VERSION 5.8 ;
BUSBITCHARS "[]" ;
DIVIDERCHAR "/" ;
UNITS
    DATABASE MICRONS 1000 ;
END UNITS

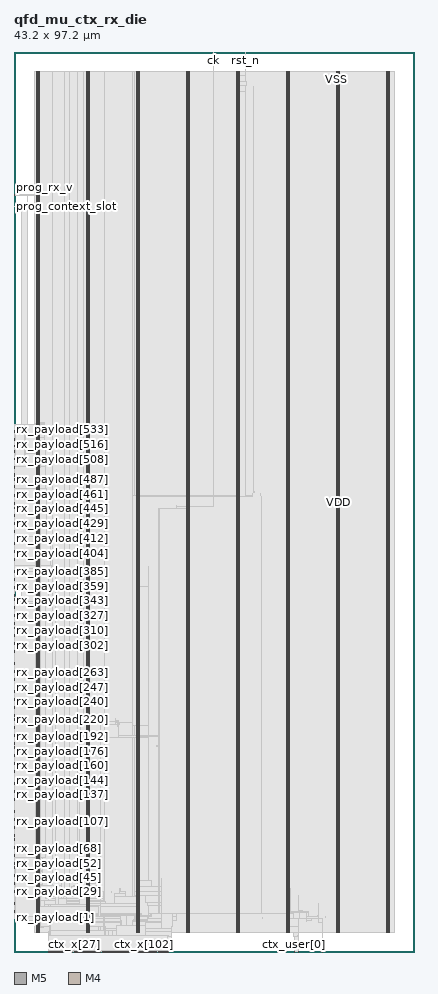
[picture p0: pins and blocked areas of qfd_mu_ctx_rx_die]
MACRO qfd_mu_ctx_rx_die
  FOREIGN qfd_mu_ctx_rx_die 0 0 ;
  CLASS BLOCK ;
  SIZE 43.2 BY 97.2 ;
  PIN ck
    DIRECTION INPUT ;
    USE SIGNAL ;
    PORT
      LAYER M5 ;
        RECT  21.504 97.116 21.528 97.2 ;
    END
  END ck
  PIN ctx_user[0]
    DIRECTION OUTPUT ;
    USE SIGNAL ;
    PORT
      LAYER M5 ;
        RECT  30.24 0 30.264 0.084 ;
    END
  END ctx_user[0]
  PIN ctx_user[1]
    DIRECTION OUTPUT ;
    USE SIGNAL ;
    PORT
      LAYER M5 ;
        RECT  30.72 0 30.744 0.084 ;
    END
  END ctx_user[1]
  PIN ctx_x[0]
    DIRECTION OUTPUT ;
    USE SIGNAL ;
    PORT
      LAYER M5 ;
        RECT  3.744 0 3.768 0.084 ;
    END
  END ctx_x[0]
  PIN ctx_x[100]
    DIRECTION OUTPUT ;
    USE SIGNAL ;
    PORT
      LAYER M5 ;
        RECT  13.824 0 13.848 0.084 ;
    END
  END ctx_x[100]
  PIN ctx_x[101]
    DIRECTION OUTPUT ;
    USE SIGNAL ;
    PORT
      LAYER M5 ;
        RECT  13.92 0 13.944 0.084 ;
    END
  END ctx_x[101]
  PIN ctx_x[102]
    DIRECTION OUTPUT ;
    USE SIGNAL ;
    PORT
      LAYER M5 ;
        RECT  14.016 0 14.04 0.084 ;
    END
  END ctx_x[102]
  PIN ctx_x[103]
    DIRECTION OUTPUT ;
    USE SIGNAL ;
    PORT
      LAYER M5 ;
        RECT  14.112 0 14.136 0.084 ;
    END
  END ctx_x[103]
  PIN ctx_x[104]
    DIRECTION OUTPUT ;
    USE SIGNAL ;
    PORT
      LAYER M5 ;
        RECT  14.208 0 14.232 0.084 ;
    END
  END ctx_x[104]
  PIN ctx_x[105]
    DIRECTION OUTPUT ;
    USE SIGNAL ;
    PORT
      LAYER M5 ;
        RECT  14.304 0 14.328 0.084 ;
    END
  END ctx_x[105]
  PIN ctx_x[106]
    DIRECTION OUTPUT ;
    USE SIGNAL ;
    PORT
      LAYER M5 ;
        RECT  14.4 0 14.424 0.084 ;
    END
  END ctx_x[106]
  PIN ctx_x[107]
    DIRECTION OUTPUT ;
    USE SIGNAL ;
    PORT
      LAYER M5 ;
        RECT  14.544 0 14.568 0.084 ;
    END
  END ctx_x[107]
  PIN ctx_x[108]
    DIRECTION OUTPUT ;
    USE SIGNAL ;
    PORT
      LAYER M5 ;
        RECT  14.64 0 14.664 0.084 ;
    END
  END ctx_x[108]
  PIN ctx_x[109]
    DIRECTION OUTPUT ;
    USE SIGNAL ;
    PORT
      LAYER M5 ;
        RECT  14.736 0 14.76 0.084 ;
    END
  END ctx_x[109]
  PIN ctx_x[10]
    DIRECTION OUTPUT ;
    USE SIGNAL ;
    PORT
      LAYER M5 ;
        RECT  4.752 0 4.776 0.084 ;
    END
  END ctx_x[10]
  PIN ctx_x[110]
    DIRECTION OUTPUT ;
    USE SIGNAL ;
    PORT
      LAYER M5 ;
        RECT  14.832 0 14.856 0.084 ;
    END
  END ctx_x[110]
  PIN ctx_x[111]
    DIRECTION OUTPUT ;
    USE SIGNAL ;
    PORT
      LAYER M5 ;
        RECT  14.928 0 14.952 0.084 ;
    END
  END ctx_x[111]
  PIN ctx_x[112]
    DIRECTION OUTPUT ;
    USE SIGNAL ;
    PORT
      LAYER M5 ;
        RECT  15.024 0 15.048 0.084 ;
    END
  END ctx_x[112]
  PIN ctx_x[113]
    DIRECTION OUTPUT ;
    USE SIGNAL ;
    PORT
      LAYER M5 ;
        RECT  15.12 0 15.144 0.084 ;
    END
  END ctx_x[113]
  PIN ctx_x[114]
    DIRECTION OUTPUT ;
    USE SIGNAL ;
    PORT
      LAYER M5 ;
        RECT  15.216 0 15.24 0.084 ;
    END
  END ctx_x[114]
  PIN ctx_x[115]
    DIRECTION OUTPUT ;
    USE SIGNAL ;
    PORT
      LAYER M5 ;
        RECT  15.312 0 15.336 0.084 ;
    END
  END ctx_x[115]
  PIN ctx_x[116]
    DIRECTION OUTPUT ;
    USE SIGNAL ;
    PORT
      LAYER M5 ;
        RECT  15.408 0 15.432 0.084 ;
    END
  END ctx_x[116]
  PIN ctx_x[117]
    DIRECTION OUTPUT ;
    USE SIGNAL ;
    PORT
      LAYER M5 ;
        RECT  15.552 0 15.576 0.084 ;
    END
  END ctx_x[117]
  PIN ctx_x[118]
    DIRECTION OUTPUT ;
    USE SIGNAL ;
    PORT
      LAYER M5 ;
        RECT  15.648 0 15.672 0.084 ;
    END
  END ctx_x[118]
  PIN ctx_x[119]
    DIRECTION OUTPUT ;
    USE SIGNAL ;
    PORT
      LAYER M5 ;
        RECT  15.744 0 15.768 0.084 ;
    END
  END ctx_x[119]
  PIN ctx_x[11]
    DIRECTION OUTPUT ;
    USE SIGNAL ;
    PORT
      LAYER M5 ;
        RECT  4.848 0 4.872 0.084 ;
    END
  END ctx_x[11]
  PIN ctx_x[120]
    DIRECTION OUTPUT ;
    USE SIGNAL ;
    PORT
      LAYER M5 ;
        RECT  15.84 0 15.864 0.084 ;
    END
  END ctx_x[120]
  PIN ctx_x[121]
    DIRECTION OUTPUT ;
    USE SIGNAL ;
    PORT
      LAYER M5 ;
        RECT  15.936 0 15.96 0.084 ;
    END
  END ctx_x[121]
  PIN ctx_x[122]
    DIRECTION OUTPUT ;
    USE SIGNAL ;
    PORT
      LAYER M5 ;
        RECT  16.032 0 16.056 0.084 ;
    END
  END ctx_x[122]
  PIN ctx_x[123]
    DIRECTION OUTPUT ;
    USE SIGNAL ;
    PORT
      LAYER M5 ;
        RECT  16.128 0 16.152 0.084 ;
    END
  END ctx_x[123]
  PIN ctx_x[124]
    DIRECTION OUTPUT ;
    USE SIGNAL ;
    PORT
      LAYER M5 ;
        RECT  16.224 0 16.248 0.084 ;
    END
  END ctx_x[124]
  PIN ctx_x[125]
    DIRECTION OUTPUT ;
    USE SIGNAL ;
    PORT
      LAYER M5 ;
        RECT  16.32 0 16.344 0.084 ;
    END
  END ctx_x[125]
  PIN ctx_x[126]
    DIRECTION OUTPUT ;
    USE SIGNAL ;
    PORT
      LAYER M5 ;
        RECT  16.416 0 16.44 0.084 ;
    END
  END ctx_x[126]
  PIN ctx_x[127]
    DIRECTION OUTPUT ;
    USE SIGNAL ;
    PORT
      LAYER M5 ;
        RECT  16.56 0 16.584 0.084 ;
    END
  END ctx_x[127]
  PIN ctx_x[128]
    DIRECTION OUTPUT ;
    USE SIGNAL ;
    PORT
      LAYER M5 ;
        RECT  16.656 0 16.68 0.084 ;
    END
  END ctx_x[128]
  PIN ctx_x[12]
    DIRECTION OUTPUT ;
    USE SIGNAL ;
    PORT
      LAYER M5 ;
        RECT  4.944 0 4.968 0.084 ;
    END
  END ctx_x[12]
  PIN ctx_x[13]
    DIRECTION OUTPUT ;
    USE SIGNAL ;
    PORT
      LAYER M5 ;
        RECT  5.04 0 5.064 0.084 ;
    END
  END ctx_x[13]
  PIN ctx_x[14]
    DIRECTION OUTPUT ;
    USE SIGNAL ;
    PORT
      LAYER M5 ;
        RECT  5.136 0 5.16 0.084 ;
    END
  END ctx_x[14]
  PIN ctx_x[15]
    DIRECTION OUTPUT ;
    USE SIGNAL ;
    PORT
      LAYER M5 ;
        RECT  5.232 0 5.256 0.084 ;
    END
  END ctx_x[15]
  PIN ctx_x[16]
    DIRECTION OUTPUT ;
    USE SIGNAL ;
    PORT
      LAYER M5 ;
        RECT  5.328 0 5.352 0.084 ;
    END
  END ctx_x[16]
  PIN ctx_x[17]
    DIRECTION OUTPUT ;
    USE SIGNAL ;
    PORT
      LAYER M5 ;
        RECT  5.472 0 5.496 0.084 ;
    END
  END ctx_x[17]
  PIN ctx_x[18]
    DIRECTION OUTPUT ;
    USE SIGNAL ;
    PORT
      LAYER M5 ;
        RECT  5.568 0 5.592 0.084 ;
    END
  END ctx_x[18]
  PIN ctx_x[19]
    DIRECTION OUTPUT ;
    USE SIGNAL ;
    PORT
      LAYER M5 ;
        RECT  5.664 0 5.688 0.084 ;
    END
  END ctx_x[19]
  PIN ctx_x[1]
    DIRECTION OUTPUT ;
    USE SIGNAL ;
    PORT
      LAYER M5 ;
        RECT  3.84 0 3.864 0.084 ;
    END
  END ctx_x[1]
  PIN ctx_x[20]
    DIRECTION OUTPUT ;
    USE SIGNAL ;
    PORT
      LAYER M5 ;
        RECT  5.76 0 5.784 0.084 ;
    END
  END ctx_x[20]
  PIN ctx_x[21]
    DIRECTION OUTPUT ;
    USE SIGNAL ;
    PORT
      LAYER M5 ;
        RECT  5.856 0 5.88 0.084 ;
    END
  END ctx_x[21]
  PIN ctx_x[22]
    DIRECTION OUTPUT ;
    USE SIGNAL ;
    PORT
      LAYER M5 ;
        RECT  5.952 0 5.976 0.084 ;
    END
  END ctx_x[22]
  PIN ctx_x[23]
    DIRECTION OUTPUT ;
    USE SIGNAL ;
    PORT
      LAYER M5 ;
        RECT  6.048 0 6.072 0.084 ;
    END
  END ctx_x[23]
  PIN ctx_x[24]
    DIRECTION OUTPUT ;
    USE SIGNAL ;
    PORT
      LAYER M5 ;
        RECT  6.144 0 6.168 0.084 ;
    END
  END ctx_x[24]
  PIN ctx_x[25]
    DIRECTION OUTPUT ;
    USE SIGNAL ;
    PORT
      LAYER M5 ;
        RECT  6.24 0 6.264 0.084 ;
    END
  END ctx_x[25]
  PIN ctx_x[26]
    DIRECTION OUTPUT ;
    USE SIGNAL ;
    PORT
      LAYER M5 ;
        RECT  6.336 0 6.36 0.084 ;
    END
  END ctx_x[26]
  PIN ctx_x[27]
    DIRECTION OUTPUT ;
    USE SIGNAL ;
    PORT
      LAYER M5 ;
        RECT  6.48 0 6.504 0.084 ;
    END
  END ctx_x[27]
  PIN ctx_x[28]
    DIRECTION OUTPUT ;
    USE SIGNAL ;
    PORT
      LAYER M5 ;
        RECT  6.576 0 6.6 0.084 ;
    END
  END ctx_x[28]
  PIN ctx_x[29]
    DIRECTION OUTPUT ;
    USE SIGNAL ;
    PORT
      LAYER M5 ;
        RECT  6.672 0 6.696 0.084 ;
    END
  END ctx_x[29]
  PIN ctx_x[2]
    DIRECTION OUTPUT ;
    USE SIGNAL ;
    PORT
      LAYER M5 ;
        RECT  3.936 0 3.96 0.084 ;
    END
  END ctx_x[2]
  PIN ctx_x[30]
    DIRECTION OUTPUT ;
    USE SIGNAL ;
    PORT
      LAYER M5 ;
        RECT  6.768 0 6.792 0.084 ;
    END
  END ctx_x[30]
  PIN ctx_x[31]
    DIRECTION OUTPUT ;
    USE SIGNAL ;
    PORT
      LAYER M5 ;
        RECT  6.864 0 6.888 0.084 ;
    END
  END ctx_x[31]
  PIN ctx_x[32]
    DIRECTION OUTPUT ;
    USE SIGNAL ;
    PORT
      LAYER M5 ;
        RECT  6.96 0 6.984 0.084 ;
    END
  END ctx_x[32]
  PIN ctx_x[33]
    DIRECTION OUTPUT ;
    USE SIGNAL ;
    PORT
      LAYER M5 ;
        RECT  7.056 0 7.08 0.084 ;
    END
  END ctx_x[33]
  PIN ctx_x[34]
    DIRECTION OUTPUT ;
    USE SIGNAL ;
    PORT
      LAYER M5 ;
        RECT  7.152 0 7.176 0.084 ;
    END
  END ctx_x[34]
  PIN ctx_x[35]
    DIRECTION OUTPUT ;
    USE SIGNAL ;
    PORT
      LAYER M5 ;
        RECT  7.248 0 7.272 0.084 ;
    END
  END ctx_x[35]
  PIN ctx_x[36]
    DIRECTION OUTPUT ;
    USE SIGNAL ;
    PORT
      LAYER M5 ;
        RECT  7.344 0 7.368 0.084 ;
    END
  END ctx_x[36]
  PIN ctx_x[37]
    DIRECTION OUTPUT ;
    USE SIGNAL ;
    PORT
      LAYER M5 ;
        RECT  7.488 0 7.512 0.084 ;
    END
  END ctx_x[37]
  PIN ctx_x[38]
    DIRECTION OUTPUT ;
    USE SIGNAL ;
    PORT
      LAYER M5 ;
        RECT  7.584 0 7.608 0.084 ;
    END
  END ctx_x[38]
  PIN ctx_x[39]
    DIRECTION OUTPUT ;
    USE SIGNAL ;
    PORT
      LAYER M5 ;
        RECT  7.68 0 7.704 0.084 ;
    END
  END ctx_x[39]
  PIN ctx_x[3]
    DIRECTION OUTPUT ;
    USE SIGNAL ;
    PORT
      LAYER M5 ;
        RECT  4.032 0 4.056 0.084 ;
    END
  END ctx_x[3]
  PIN ctx_x[40]
    DIRECTION OUTPUT ;
    USE SIGNAL ;
    PORT
      LAYER M5 ;
        RECT  7.776 0 7.8 0.084 ;
    END
  END ctx_x[40]
  PIN ctx_x[41]
    DIRECTION OUTPUT ;
    USE SIGNAL ;
    PORT
      LAYER M5 ;
        RECT  7.872 0 7.896 0.084 ;
    END
  END ctx_x[41]
  PIN ctx_x[42]
    DIRECTION OUTPUT ;
    USE SIGNAL ;
    PORT
      LAYER M5 ;
        RECT  7.968 0 7.992 0.084 ;
    END
  END ctx_x[42]
  PIN ctx_x[43]
    DIRECTION OUTPUT ;
    USE SIGNAL ;
    PORT
      LAYER M5 ;
        RECT  8.064 0 8.088 0.084 ;
    END
  END ctx_x[43]
  PIN ctx_x[44]
    DIRECTION OUTPUT ;
    USE SIGNAL ;
    PORT
      LAYER M5 ;
        RECT  8.16 0 8.184 0.084 ;
    END
  END ctx_x[44]
  PIN ctx_x[45]
    DIRECTION OUTPUT ;
    USE SIGNAL ;
    PORT
      LAYER M5 ;
        RECT  8.256 0 8.28 0.084 ;
    END
  END ctx_x[45]
  PIN ctx_x[46]
    DIRECTION OUTPUT ;
    USE SIGNAL ;
    PORT
      LAYER M5 ;
        RECT  8.352 0 8.376 0.084 ;
    END
  END ctx_x[46]
  PIN ctx_x[47]
    DIRECTION OUTPUT ;
    USE SIGNAL ;
    PORT
      LAYER M5 ;
        RECT  8.496 0 8.52 0.084 ;
    END
  END ctx_x[47]
  PIN ctx_x[48]
    DIRECTION OUTPUT ;
    USE SIGNAL ;
    PORT
      LAYER M5 ;
        RECT  8.592 0 8.616 0.084 ;
    END
  END ctx_x[48]
  PIN ctx_x[49]
    DIRECTION OUTPUT ;
    USE SIGNAL ;
    PORT
      LAYER M5 ;
        RECT  8.688 0 8.712 0.084 ;
    END
  END ctx_x[49]
  PIN ctx_x[4]
    DIRECTION OUTPUT ;
    USE SIGNAL ;
    PORT
      LAYER M5 ;
        RECT  4.128 0 4.152 0.084 ;
    END
  END ctx_x[4]
  PIN ctx_x[50]
    DIRECTION OUTPUT ;
    USE SIGNAL ;
    PORT
      LAYER M5 ;
        RECT  8.784 0 8.808 0.084 ;
    END
  END ctx_x[50]
  PIN ctx_x[51]
    DIRECTION OUTPUT ;
    USE SIGNAL ;
    PORT
      LAYER M5 ;
        RECT  8.88 0 8.904 0.084 ;
    END
  END ctx_x[51]
  PIN ctx_x[52]
    DIRECTION OUTPUT ;
    USE SIGNAL ;
    PORT
      LAYER M5 ;
        RECT  8.976 0 9 0.084 ;
    END
  END ctx_x[52]
  PIN ctx_x[53]
    DIRECTION OUTPUT ;
    USE SIGNAL ;
    PORT
      LAYER M5 ;
        RECT  9.072 0 9.096 0.084 ;
    END
  END ctx_x[53]
  PIN ctx_x[54]
    DIRECTION OUTPUT ;
    USE SIGNAL ;
    PORT
      LAYER M5 ;
        RECT  9.168 0 9.192 0.084 ;
    END
  END ctx_x[54]
  PIN ctx_x[55]
    DIRECTION OUTPUT ;
    USE SIGNAL ;
    PORT
      LAYER M5 ;
        RECT  9.264 0 9.288 0.084 ;
    END
  END ctx_x[55]
  PIN ctx_x[56]
    DIRECTION OUTPUT ;
    USE SIGNAL ;
    PORT
      LAYER M5 ;
        RECT  9.36 0 9.384 0.084 ;
    END
  END ctx_x[56]
  PIN ctx_x[57]
    DIRECTION OUTPUT ;
    USE SIGNAL ;
    PORT
      LAYER M5 ;
        RECT  9.504 0 9.528 0.084 ;
    END
  END ctx_x[57]
  PIN ctx_x[58]
    DIRECTION OUTPUT ;
    USE SIGNAL ;
    PORT
      LAYER M5 ;
        RECT  9.6 0 9.624 0.084 ;
    END
  END ctx_x[58]
  PIN ctx_x[59]
    DIRECTION OUTPUT ;
    USE SIGNAL ;
    PORT
      LAYER M5 ;
        RECT  9.696 0 9.72 0.084 ;
    END
  END ctx_x[59]
  PIN ctx_x[5]
    DIRECTION OUTPUT ;
    USE SIGNAL ;
    PORT
      LAYER M5 ;
        RECT  4.224 0 4.248 0.084 ;
    END
  END ctx_x[5]
  PIN ctx_x[60]
    DIRECTION OUTPUT ;
    USE SIGNAL ;
    PORT
      LAYER M5 ;
        RECT  9.792 0 9.816 0.084 ;
    END
  END ctx_x[60]
  PIN ctx_x[61]
    DIRECTION OUTPUT ;
    USE SIGNAL ;
    PORT
      LAYER M5 ;
        RECT  9.888 0 9.912 0.084 ;
    END
  END ctx_x[61]
  PIN ctx_x[62]
    DIRECTION OUTPUT ;
    USE SIGNAL ;
    PORT
      LAYER M5 ;
        RECT  9.984 0 10.008 0.084 ;
    END
  END ctx_x[62]
  PIN ctx_x[63]
    DIRECTION OUTPUT ;
    USE SIGNAL ;
    PORT
      LAYER M5 ;
        RECT  10.08 0 10.104 0.084 ;
    END
  END ctx_x[63]
  PIN ctx_x[64]
    DIRECTION OUTPUT ;
    USE SIGNAL ;
    PORT
      LAYER M5 ;
        RECT  10.176 0 10.2 0.084 ;
    END
  END ctx_x[64]
  PIN ctx_x[65]
    DIRECTION OUTPUT ;
    USE SIGNAL ;
    PORT
      LAYER M5 ;
        RECT  10.272 0 10.296 0.084 ;
    END
  END ctx_x[65]
  PIN ctx_x[66]
    DIRECTION OUTPUT ;
    USE SIGNAL ;
    PORT
      LAYER M5 ;
        RECT  10.368 0 10.392 0.084 ;
    END
  END ctx_x[66]
  PIN ctx_x[67]
    DIRECTION OUTPUT ;
    USE SIGNAL ;
    PORT
      LAYER M5 ;
        RECT  10.512 0 10.536 0.084 ;
    END
  END ctx_x[67]
  PIN ctx_x[68]
    DIRECTION OUTPUT ;
    USE SIGNAL ;
    PORT
      LAYER M5 ;
        RECT  10.608 0 10.632 0.084 ;
    END
  END ctx_x[68]
  PIN ctx_x[69]
    DIRECTION OUTPUT ;
    USE SIGNAL ;
    PORT
      LAYER M5 ;
        RECT  10.704 0 10.728 0.084 ;
    END
  END ctx_x[69]
  PIN ctx_x[6]
    DIRECTION OUTPUT ;
    USE SIGNAL ;
    PORT
      LAYER M5 ;
        RECT  4.32 0 4.344 0.084 ;
    END
  END ctx_x[6]
  PIN ctx_x[70]
    DIRECTION OUTPUT ;
    USE SIGNAL ;
    PORT
      LAYER M5 ;
        RECT  10.8 0 10.824 0.084 ;
    END
  END ctx_x[70]
  PIN ctx_x[71]
    DIRECTION OUTPUT ;
    USE SIGNAL ;
    PORT
      LAYER M5 ;
        RECT  10.896 0 10.92 0.084 ;
    END
  END ctx_x[71]
  PIN ctx_x[72]
    DIRECTION OUTPUT ;
    USE SIGNAL ;
    PORT
      LAYER M5 ;
        RECT  10.992 0 11.016 0.084 ;
    END
  END ctx_x[72]
  PIN ctx_x[73]
    DIRECTION OUTPUT ;
    USE SIGNAL ;
    PORT
      LAYER M5 ;
        RECT  11.088 0 11.112 0.084 ;
    END
  END ctx_x[73]
  PIN ctx_x[74]
    DIRECTION OUTPUT ;
    USE SIGNAL ;
    PORT
      LAYER M5 ;
        RECT  11.184 0 11.208 0.084 ;
    END
  END ctx_x[74]
  PIN ctx_x[75]
    DIRECTION OUTPUT ;
    USE SIGNAL ;
    PORT
      LAYER M5 ;
        RECT  11.28 0 11.304 0.084 ;
    END
  END ctx_x[75]
  PIN ctx_x[76]
    DIRECTION OUTPUT ;
    USE SIGNAL ;
    PORT
      LAYER M5 ;
        RECT  11.376 0 11.4 0.084 ;
    END
  END ctx_x[76]
  PIN ctx_x[77]
    DIRECTION OUTPUT ;
    USE SIGNAL ;
    PORT
      LAYER M5 ;
        RECT  11.52 0 11.544 0.084 ;
    END
  END ctx_x[77]
  PIN ctx_x[78]
    DIRECTION OUTPUT ;
    USE SIGNAL ;
    PORT
      LAYER M5 ;
        RECT  11.616 0 11.64 0.084 ;
    END
  END ctx_x[78]
  PIN ctx_x[79]
    DIRECTION OUTPUT ;
    USE SIGNAL ;
    PORT
      LAYER M5 ;
        RECT  11.712 0 11.736 0.084 ;
    END
  END ctx_x[79]
  PIN ctx_x[7]
    DIRECTION OUTPUT ;
    USE SIGNAL ;
    PORT
      LAYER M5 ;
        RECT  4.464 0 4.488 0.084 ;
    END
  END ctx_x[7]
  PIN ctx_x[80]
    DIRECTION OUTPUT ;
    USE SIGNAL ;
    PORT
      LAYER M5 ;
        RECT  11.808 0 11.832 0.084 ;
    END
  END ctx_x[80]
  PIN ctx_x[81]
    DIRECTION OUTPUT ;
    USE SIGNAL ;
    PORT
      LAYER M5 ;
        RECT  11.904 0 11.928 0.084 ;
    END
  END ctx_x[81]
  PIN ctx_x[82]
    DIRECTION OUTPUT ;
    USE SIGNAL ;
    PORT
      LAYER M5 ;
        RECT  12 0 12.024 0.084 ;
    END
  END ctx_x[82]
  PIN ctx_x[83]
    DIRECTION OUTPUT ;
    USE SIGNAL ;
    PORT
      LAYER M5 ;
        RECT  12.096 0 12.12 0.084 ;
    END
  END ctx_x[83]
  PIN ctx_x[84]
    DIRECTION OUTPUT ;
    USE SIGNAL ;
    PORT
      LAYER M5 ;
        RECT  12.192 0 12.216 0.084 ;
    END
  END ctx_x[84]
  PIN ctx_x[85]
    DIRECTION OUTPUT ;
    USE SIGNAL ;
    PORT
      LAYER M5 ;
        RECT  12.288 0 12.312 0.084 ;
    END
  END ctx_x[85]
  PIN ctx_x[86]
    DIRECTION OUTPUT ;
    USE SIGNAL ;
    PORT
      LAYER M5 ;
        RECT  12.384 0 12.408 0.084 ;
    END
  END ctx_x[86]
  PIN ctx_x[87]
    DIRECTION OUTPUT ;
    USE SIGNAL ;
    PORT
      LAYER M5 ;
        RECT  12.528 0 12.552 0.084 ;
    END
  END ctx_x[87]
  PIN ctx_x[88]
    DIRECTION OUTPUT ;
    USE SIGNAL ;
    PORT
      LAYER M5 ;
        RECT  12.624 0 12.648 0.084 ;
    END
  END ctx_x[88]
  PIN ctx_x[89]
    DIRECTION OUTPUT ;
    USE SIGNAL ;
    PORT
      LAYER M5 ;
        RECT  12.72 0 12.744 0.084 ;
    END
  END ctx_x[89]
  PIN ctx_x[8]
    DIRECTION OUTPUT ;
    USE SIGNAL ;
    PORT
      LAYER M5 ;
        RECT  4.56 0 4.584 0.084 ;
    END
  END ctx_x[8]
  PIN ctx_x[90]
    DIRECTION OUTPUT ;
    USE SIGNAL ;
    PORT
      LAYER M5 ;
        RECT  12.816 0 12.84 0.084 ;
    END
  END ctx_x[90]
  PIN ctx_x[91]
    DIRECTION OUTPUT ;
    USE SIGNAL ;
    PORT
      LAYER M5 ;
        RECT  12.912 0 12.936 0.084 ;
    END
  END ctx_x[91]
  PIN ctx_x[92]
    DIRECTION OUTPUT ;
    USE SIGNAL ;
    PORT
      LAYER M5 ;
        RECT  13.008 0 13.032 0.084 ;
    END
  END ctx_x[92]
  PIN ctx_x[93]
    DIRECTION OUTPUT ;
    USE SIGNAL ;
    PORT
      LAYER M5 ;
        RECT  13.104 0 13.128 0.084 ;
    END
  END ctx_x[93]
  PIN ctx_x[94]
    DIRECTION OUTPUT ;
    USE SIGNAL ;
    PORT
      LAYER M5 ;
        RECT  13.2 0 13.224 0.084 ;
    END
  END ctx_x[94]
  PIN ctx_x[95]
    DIRECTION OUTPUT ;
    USE SIGNAL ;
    PORT
      LAYER M5 ;
        RECT  13.296 0 13.32 0.084 ;
    END
  END ctx_x[95]
  PIN ctx_x[96]
    DIRECTION OUTPUT ;
    USE SIGNAL ;
    PORT
      LAYER M5 ;
        RECT  13.392 0 13.416 0.084 ;
    END
  END ctx_x[96]
  PIN ctx_x[97]
    DIRECTION OUTPUT ;
    USE SIGNAL ;
    PORT
      LAYER M5 ;
        RECT  13.536 0 13.56 0.084 ;
    END
  END ctx_x[97]
  PIN ctx_x[98]
    DIRECTION OUTPUT ;
    USE SIGNAL ;
    PORT
      LAYER M5 ;
        RECT  13.632 0 13.656 0.084 ;
    END
  END ctx_x[98]
  PIN ctx_x[99]
    DIRECTION OUTPUT ;
    USE SIGNAL ;
    PORT
      LAYER M5 ;
        RECT  13.728 0 13.752 0.084 ;
    END
  END ctx_x[99]
  PIN ctx_x[9]
    DIRECTION OUTPUT ;
    USE SIGNAL ;
    PORT
      LAYER M5 ;
        RECT  4.656 0 4.68 0.084 ;
    END
  END ctx_x[9]
  PIN mu_fault
    DIRECTION OUTPUT ;
    USE SIGNAL ;
    PORT
      LAYER M5 ;
        RECT  33.312 0 33.336 0.084 ;
    END
  END mu_fault
  PIN prog_context_slot
    DIRECTION INPUT ;
    USE SIGNAL ;
    PORT
      LAYER M4 ;
        RECT  0 80.544 0.084 80.568 ;
    END
  END prog_context_slot
  PIN prog_rx_v
    DIRECTION INPUT ;
    USE SIGNAL ;
    PORT
      LAYER M4 ;
        RECT  0 81.744 0.084 81.768 ;
    END
  END prog_rx_v
  PIN rst_n
    DIRECTION INPUT ;
    USE SIGNAL ;
    PORT
      LAYER M5 ;
        RECT  25.008 97.116 25.032 97.2 ;
    END
  END rst_n
  PIN rx_payload[0]
    DIRECTION INPUT ;
    USE SIGNAL ;
    PORT
      LAYER M4 ;
        RECT  0 3.648 0.084 3.672 ;
    END
  END rx_payload[0]
  PIN rx_payload[100]
    DIRECTION INPUT ;
    USE SIGNAL ;
    PORT
      LAYER M4 ;
        RECT  0 13.392 0.084 13.416 ;
    END
  END rx_payload[100]
  PIN rx_payload[101]
    DIRECTION INPUT ;
    USE SIGNAL ;
    PORT
      LAYER M4 ;
        RECT  0 13.488 0.084 13.512 ;
    END
  END rx_payload[101]
  PIN rx_payload[102]
    DIRECTION INPUT ;
    USE SIGNAL ;
    PORT
      LAYER M4 ;
        RECT  0 13.584 0.084 13.608 ;
    END
  END rx_payload[102]
  PIN rx_payload[103]
    DIRECTION INPUT ;
    USE SIGNAL ;
    PORT
      LAYER M4 ;
        RECT  0 13.68 0.084 13.704 ;
    END
  END rx_payload[103]
  PIN rx_payload[104]
    DIRECTION INPUT ;
    USE SIGNAL ;
    PORT
      LAYER M4 ;
        RECT  0 13.776 0.084 13.8 ;
    END
  END rx_payload[104]
  PIN rx_payload[105]
    DIRECTION INPUT ;
    USE SIGNAL ;
    PORT
      LAYER M4 ;
        RECT  0 13.872 0.084 13.896 ;
    END
  END rx_payload[105]
  PIN rx_payload[106]
    DIRECTION INPUT ;
    USE SIGNAL ;
    PORT
      LAYER M4 ;
        RECT  0 13.968 0.084 13.992 ;
    END
  END rx_payload[106]
  PIN rx_payload[107]
    DIRECTION INPUT ;
    USE SIGNAL ;
    PORT
      LAYER M4 ;
        RECT  0 14.064 0.084 14.088 ;
    END
  END rx_payload[107]
  PIN rx_payload[108]
    DIRECTION INPUT ;
    USE SIGNAL ;
    PORT
      LAYER M4 ;
        RECT  0 14.16 0.084 14.184 ;
    END
  END rx_payload[108]
  PIN rx_payload[109]
    DIRECTION INPUT ;
    USE SIGNAL ;
    PORT
      LAYER M4 ;
        RECT  0 14.256 0.084 14.28 ;
    END
  END rx_payload[109]
  PIN rx_payload[10]
    DIRECTION INPUT ;
    USE SIGNAL ;
    PORT
      LAYER M4 ;
        RECT  0 4.608 0.084 4.632 ;
    END
  END rx_payload[10]
  PIN rx_payload[110]
    DIRECTION INPUT ;
    USE SIGNAL ;
    PORT
      LAYER M4 ;
        RECT  0 14.352 0.084 14.376 ;
    END
  END rx_payload[110]
  PIN rx_payload[111]
    DIRECTION INPUT ;
    USE SIGNAL ;
    PORT
      LAYER M4 ;
        RECT  0 14.448 0.084 14.472 ;
    END
  END rx_payload[111]
  PIN rx_payload[112]
    DIRECTION INPUT ;
    USE SIGNAL ;
    PORT
      LAYER M4 ;
        RECT  0 14.544 0.084 14.568 ;
    END
  END rx_payload[112]
  PIN rx_payload[113]
    DIRECTION INPUT ;
    USE SIGNAL ;
    PORT
      LAYER M4 ;
        RECT  0 14.64 0.084 14.664 ;
    END
  END rx_payload[113]
  PIN rx_payload[114]
    DIRECTION INPUT ;
    USE SIGNAL ;
    PORT
      LAYER M4 ;
        RECT  0 14.736 0.084 14.76 ;
    END
  END rx_payload[114]
  PIN rx_payload[115]
    DIRECTION INPUT ;
    USE SIGNAL ;
    PORT
      LAYER M4 ;
        RECT  0 14.832 0.084 14.856 ;
    END
  END rx_payload[115]
  PIN rx_payload[116]
    DIRECTION INPUT ;
    USE SIGNAL ;
    PORT
      LAYER M4 ;
        RECT  0 14.928 0.084 14.952 ;
    END
  END rx_payload[116]
  PIN rx_payload[117]
    DIRECTION INPUT ;
    USE SIGNAL ;
    PORT
      LAYER M4 ;
        RECT  0 15.024 0.084 15.048 ;
    END
  END rx_payload[117]
  PIN rx_payload[118]
    DIRECTION INPUT ;
    USE SIGNAL ;
    PORT
      LAYER M4 ;
        RECT  0 15.12 0.084 15.144 ;
    END
  END rx_payload[118]
  PIN rx_payload[119]
    DIRECTION INPUT ;
    USE SIGNAL ;
    PORT
      LAYER M4 ;
        RECT  0 15.216 0.084 15.24 ;
    END
  END rx_payload[119]
  PIN rx_payload[11]
    DIRECTION INPUT ;
    USE SIGNAL ;
    PORT
      LAYER M4 ;
        RECT  0 4.704 0.084 4.728 ;
    END
  END rx_payload[11]
  PIN rx_payload[120]
    DIRECTION INPUT ;
    USE SIGNAL ;
    PORT
      LAYER M4 ;
        RECT  0 15.312 0.084 15.336 ;
    END
  END rx_payload[120]
  PIN rx_payload[121]
    DIRECTION INPUT ;
    USE SIGNAL ;
    PORT
      LAYER M4 ;
        RECT  0 15.408 0.084 15.432 ;
    END
  END rx_payload[121]
  PIN rx_payload[122]
    DIRECTION INPUT ;
    USE SIGNAL ;
    PORT
      LAYER M4 ;
        RECT  0 15.504 0.084 15.528 ;
    END
  END rx_payload[122]
  PIN rx_payload[123]
    DIRECTION INPUT ;
    USE SIGNAL ;
    PORT
      LAYER M4 ;
        RECT  0 15.6 0.084 15.624 ;
    END
  END rx_payload[123]
  PIN rx_payload[124]
    DIRECTION INPUT ;
    USE SIGNAL ;
    PORT
      LAYER M4 ;
        RECT  0 15.744 0.084 15.768 ;
    END
  END rx_payload[124]
  PIN rx_payload[125]
    DIRECTION INPUT ;
    USE SIGNAL ;
    PORT
      LAYER M4 ;
        RECT  0 15.84 0.084 15.864 ;
    END
  END rx_payload[125]
  PIN rx_payload[126]
    DIRECTION INPUT ;
    USE SIGNAL ;
    PORT
      LAYER M4 ;
        RECT  0 15.936 0.084 15.96 ;
    END
  END rx_payload[126]
  PIN rx_payload[127]
    DIRECTION INPUT ;
    USE SIGNAL ;
    PORT
      LAYER M4 ;
        RECT  0 16.032 0.084 16.056 ;
    END
  END rx_payload[127]
  PIN rx_payload[128]
    DIRECTION INPUT ;
    USE SIGNAL ;
    PORT
      LAYER M4 ;
        RECT  0 16.128 0.084 16.152 ;
    END
  END rx_payload[128]
  PIN rx_payload[129]
    DIRECTION INPUT ;
    USE SIGNAL ;
    PORT
      LAYER M4 ;
        RECT  0 16.224 0.084 16.248 ;
    END
  END rx_payload[129]
  PIN rx_payload[12]
    DIRECTION INPUT ;
    USE SIGNAL ;
    PORT
      LAYER M4 ;
        RECT  0 4.8 0.084 4.824 ;
    END
  END rx_payload[12]
  PIN rx_payload[130]
    DIRECTION INPUT ;
    USE SIGNAL ;
    PORT
      LAYER M4 ;
        RECT  0 16.32 0.084 16.344 ;
    END
  END rx_payload[130]
  PIN rx_payload[131]
    DIRECTION INPUT ;
    USE SIGNAL ;
    PORT
      LAYER M4 ;
        RECT  0 16.416 0.084 16.44 ;
    END
  END rx_payload[131]
  PIN rx_payload[132]
    DIRECTION INPUT ;
    USE SIGNAL ;
    PORT
      LAYER M4 ;
        RECT  0 16.512 0.084 16.536 ;
    END
  END rx_payload[132]
  PIN rx_payload[133]
    DIRECTION INPUT ;
    USE SIGNAL ;
    PORT
      LAYER M4 ;
        RECT  0 16.608 0.084 16.632 ;
    END
  END rx_payload[133]
  PIN rx_payload[134]
    DIRECTION INPUT ;
    USE SIGNAL ;
    PORT
      LAYER M4 ;
        RECT  0 16.704 0.084 16.728 ;
    END
  END rx_payload[134]
  PIN rx_payload[135]
    DIRECTION INPUT ;
    USE SIGNAL ;
    PORT
      LAYER M4 ;
        RECT  0 16.8 0.084 16.824 ;
    END
  END rx_payload[135]
  PIN rx_payload[136]
    DIRECTION INPUT ;
    USE SIGNAL ;
    PORT
      LAYER M4 ;
        RECT  0 16.896 0.084 16.92 ;
    END
  END rx_payload[136]
  PIN rx_payload[137]
    DIRECTION INPUT ;
    USE SIGNAL ;
    PORT
      LAYER M4 ;
        RECT  0 16.992 0.084 17.016 ;
    END
  END rx_payload[137]
  PIN rx_payload[138]
    DIRECTION INPUT ;
    USE SIGNAL ;
    PORT
      LAYER M4 ;
        RECT  0 17.088 0.084 17.112 ;
    END
  END rx_payload[138]
  PIN rx_payload[139]
    DIRECTION INPUT ;
    USE SIGNAL ;
    PORT
      LAYER M4 ;
        RECT  0 17.184 0.084 17.208 ;
    END
  END rx_payload[139]
  PIN rx_payload[13]
    DIRECTION INPUT ;
    USE SIGNAL ;
    PORT
      LAYER M4 ;
        RECT  0 4.896 0.084 4.92 ;
    END
  END rx_payload[13]
  PIN rx_payload[140]
    DIRECTION INPUT ;
    USE SIGNAL ;
    PORT
      LAYER M4 ;
        RECT  0 17.28 0.084 17.304 ;
    END
  END rx_payload[140]
  PIN rx_payload[141]
    DIRECTION INPUT ;
    USE SIGNAL ;
    PORT
      LAYER M4 ;
        RECT  0 17.376 0.084 17.4 ;
    END
  END rx_payload[141]
  PIN rx_payload[142]
    DIRECTION INPUT ;
    USE SIGNAL ;
    PORT
      LAYER M4 ;
        RECT  0 17.472 0.084 17.496 ;
    END
  END rx_payload[142]
  PIN rx_payload[143]
    DIRECTION INPUT ;
    USE SIGNAL ;
    PORT
      LAYER M4 ;
        RECT  0 17.568 0.084 17.592 ;
    END
  END rx_payload[143]
  PIN rx_payload[144]
    DIRECTION INPUT ;
    USE SIGNAL ;
    PORT
      LAYER M4 ;
        RECT  0 17.664 0.084 17.688 ;
    END
  END rx_payload[144]
  PIN rx_payload[145]
    DIRECTION INPUT ;
    USE SIGNAL ;
    PORT
      LAYER M4 ;
        RECT  0 17.76 0.084 17.784 ;
    END
  END rx_payload[145]
  PIN rx_payload[146]
    DIRECTION INPUT ;
    USE SIGNAL ;
    PORT
      LAYER M4 ;
        RECT  0 17.856 0.084 17.88 ;
    END
  END rx_payload[146]
  PIN rx_payload[147]
    DIRECTION INPUT ;
    USE SIGNAL ;
    PORT
      LAYER M4 ;
        RECT  0 17.952 0.084 17.976 ;
    END
  END rx_payload[147]
  PIN rx_payload[148]
    DIRECTION INPUT ;
    USE SIGNAL ;
    PORT
      LAYER M4 ;
        RECT  0 18.048 0.084 18.072 ;
    END
  END rx_payload[148]
  PIN rx_payload[149]
    DIRECTION INPUT ;
    USE SIGNAL ;
    PORT
      LAYER M4 ;
        RECT  0 18.144 0.084 18.168 ;
    END
  END rx_payload[149]
  PIN rx_payload[14]
    DIRECTION INPUT ;
    USE SIGNAL ;
    PORT
      LAYER M4 ;
        RECT  0 4.992 0.084 5.016 ;
    END
  END rx_payload[14]
  PIN rx_payload[150]
    DIRECTION INPUT ;
    USE SIGNAL ;
    PORT
      LAYER M4 ;
        RECT  0 18.24 0.084 18.264 ;
    END
  END rx_payload[150]
  PIN rx_payload[151]
    DIRECTION INPUT ;
    USE SIGNAL ;
    PORT
      LAYER M4 ;
        RECT  0 18.336 0.084 18.36 ;
    END
  END rx_payload[151]
  PIN rx_payload[152]
    DIRECTION INPUT ;
    USE SIGNAL ;
    PORT
      LAYER M4 ;
        RECT  0 18.432 0.084 18.456 ;
    END
  END rx_payload[152]
  PIN rx_payload[153]
    DIRECTION INPUT ;
    USE SIGNAL ;
    PORT
      LAYER M4 ;
        RECT  0 18.528 0.084 18.552 ;
    END
  END rx_payload[153]
  PIN rx_payload[154]
    DIRECTION INPUT ;
    USE SIGNAL ;
    PORT
      LAYER M4 ;
        RECT  0 18.624 0.084 18.648 ;
    END
  END rx_payload[154]
  PIN rx_payload[155]
    DIRECTION INPUT ;
    USE SIGNAL ;
    PORT
      LAYER M4 ;
        RECT  0 18.72 0.084 18.744 ;
    END
  END rx_payload[155]
  PIN rx_payload[156]
    DIRECTION INPUT ;
    USE SIGNAL ;
    PORT
      LAYER M4 ;
        RECT  0 18.816 0.084 18.84 ;
    END
  END rx_payload[156]
  PIN rx_payload[157]
    DIRECTION INPUT ;
    USE SIGNAL ;
    PORT
      LAYER M4 ;
        RECT  0 18.96 0.084 18.984 ;
    END
  END rx_payload[157]
  PIN rx_payload[158]
    DIRECTION INPUT ;
    USE SIGNAL ;
    PORT
      LAYER M4 ;
        RECT  0 19.056 0.084 19.08 ;
    END
  END rx_payload[158]
  PIN rx_payload[159]
    DIRECTION INPUT ;
    USE SIGNAL ;
    PORT
      LAYER M4 ;
        RECT  0 19.152 0.084 19.176 ;
    END
  END rx_payload[159]
  PIN rx_payload[15]
    DIRECTION INPUT ;
    USE SIGNAL ;
    PORT
      LAYER M4 ;
        RECT  0 5.088 0.084 5.112 ;
    END
  END rx_payload[15]
  PIN rx_payload[160]
    DIRECTION INPUT ;
    USE SIGNAL ;
    PORT
      LAYER M4 ;
        RECT  0 19.248 0.084 19.272 ;
    END
  END rx_payload[160]
  PIN rx_payload[161]
    DIRECTION INPUT ;
    USE SIGNAL ;
    PORT
      LAYER M4 ;
        RECT  0 19.344 0.084 19.368 ;
    END
  END rx_payload[161]
  PIN rx_payload[162]
    DIRECTION INPUT ;
    USE SIGNAL ;
    PORT
      LAYER M4 ;
        RECT  0 19.44 0.084 19.464 ;
    END
  END rx_payload[162]
  PIN rx_payload[163]
    DIRECTION INPUT ;
    USE SIGNAL ;
    PORT
      LAYER M4 ;
        RECT  0 19.536 0.084 19.56 ;
    END
  END rx_payload[163]
  PIN rx_payload[164]
    DIRECTION INPUT ;
    USE SIGNAL ;
    PORT
      LAYER M4 ;
        RECT  0 19.632 0.084 19.656 ;
    END
  END rx_payload[164]
  PIN rx_payload[165]
    DIRECTION INPUT ;
    USE SIGNAL ;
    PORT
      LAYER M4 ;
        RECT  0 19.728 0.084 19.752 ;
    END
  END rx_payload[165]
  PIN rx_payload[166]
    DIRECTION INPUT ;
    USE SIGNAL ;
    PORT
      LAYER M4 ;
        RECT  0 19.824 0.084 19.848 ;
    END
  END rx_payload[166]
  PIN rx_payload[167]
    DIRECTION INPUT ;
    USE SIGNAL ;
    PORT
      LAYER M4 ;
        RECT  0 19.92 0.084 19.944 ;
    END
  END rx_payload[167]
  PIN rx_payload[168]
    DIRECTION INPUT ;
    USE SIGNAL ;
    PORT
      LAYER M4 ;
        RECT  0 20.016 0.084 20.04 ;
    END
  END rx_payload[168]
  PIN rx_payload[169]
    DIRECTION INPUT ;
    USE SIGNAL ;
    PORT
      LAYER M4 ;
        RECT  0 20.112 0.084 20.136 ;
    END
  END rx_payload[169]
  PIN rx_payload[16]
    DIRECTION INPUT ;
    USE SIGNAL ;
    PORT
      LAYER M4 ;
        RECT  0 5.184 0.084 5.208 ;
    END
  END rx_payload[16]
  PIN rx_payload[170]
    DIRECTION INPUT ;
    USE SIGNAL ;
    PORT
      LAYER M4 ;
        RECT  0 20.208 0.084 20.232 ;
    END
  END rx_payload[170]
  PIN rx_payload[171]
    DIRECTION INPUT ;
    USE SIGNAL ;
    PORT
      LAYER M4 ;
        RECT  0 20.304 0.084 20.328 ;
    END
  END rx_payload[171]
  PIN rx_payload[172]
    DIRECTION INPUT ;
    USE SIGNAL ;
    PORT
      LAYER M4 ;
        RECT  0 20.4 0.084 20.424 ;
    END
  END rx_payload[172]
  PIN rx_payload[173]
    DIRECTION INPUT ;
    USE SIGNAL ;
    PORT
      LAYER M4 ;
        RECT  0 20.496 0.084 20.52 ;
    END
  END rx_payload[173]
  PIN rx_payload[174]
    DIRECTION INPUT ;
    USE SIGNAL ;
    PORT
      LAYER M4 ;
        RECT  0 20.592 0.084 20.616 ;
    END
  END rx_payload[174]
  PIN rx_payload[175]
    DIRECTION INPUT ;
    USE SIGNAL ;
    PORT
      LAYER M4 ;
        RECT  0 20.688 0.084 20.712 ;
    END
  END rx_payload[175]
  PIN rx_payload[176]
    DIRECTION INPUT ;
    USE SIGNAL ;
    PORT
      LAYER M4 ;
        RECT  0 20.784 0.084 20.808 ;
    END
  END rx_payload[176]
  PIN rx_payload[177]
    DIRECTION INPUT ;
    USE SIGNAL ;
    PORT
      LAYER M4 ;
        RECT  0 20.88 0.084 20.904 ;
    END
  END rx_payload[177]
  PIN rx_payload[178]
    DIRECTION INPUT ;
    USE SIGNAL ;
    PORT
      LAYER M4 ;
        RECT  0 20.976 0.084 21 ;
    END
  END rx_payload[178]
  PIN rx_payload[179]
    DIRECTION INPUT ;
    USE SIGNAL ;
    PORT
      LAYER M4 ;
        RECT  0 21.072 0.084 21.096 ;
    END
  END rx_payload[179]
  PIN rx_payload[17]
    DIRECTION INPUT ;
    USE SIGNAL ;
    PORT
      LAYER M4 ;
        RECT  0 5.28 0.084 5.304 ;
    END
  END rx_payload[17]
  PIN rx_payload[180]
    DIRECTION INPUT ;
    USE SIGNAL ;
    PORT
      LAYER M4 ;
        RECT  0 21.168 0.084 21.192 ;
    END
  END rx_payload[180]
  PIN rx_payload[181]
    DIRECTION INPUT ;
    USE SIGNAL ;
    PORT
      LAYER M4 ;
        RECT  0 21.264 0.084 21.288 ;
    END
  END rx_payload[181]
  PIN rx_payload[182]
    DIRECTION INPUT ;
    USE SIGNAL ;
    PORT
      LAYER M4 ;
        RECT  0 21.36 0.084 21.384 ;
    END
  END rx_payload[182]
  PIN rx_payload[183]
    DIRECTION INPUT ;
    USE SIGNAL ;
    PORT
      LAYER M4 ;
        RECT  0 21.456 0.084 21.48 ;
    END
  END rx_payload[183]
  PIN rx_payload[184]
    DIRECTION INPUT ;
    USE SIGNAL ;
    PORT
      LAYER M4 ;
        RECT  0 21.552 0.084 21.576 ;
    END
  END rx_payload[184]
  PIN rx_payload[185]
    DIRECTION INPUT ;
    USE SIGNAL ;
    PORT
      LAYER M4 ;
        RECT  0 21.648 0.084 21.672 ;
    END
  END rx_payload[185]
  PIN rx_payload[186]
    DIRECTION INPUT ;
    USE SIGNAL ;
    PORT
      LAYER M4 ;
        RECT  0 21.744 0.084 21.768 ;
    END
  END rx_payload[186]
  PIN rx_payload[187]
    DIRECTION INPUT ;
    USE SIGNAL ;
    PORT
      LAYER M4 ;
        RECT  0 21.84 0.084 21.864 ;
    END
  END rx_payload[187]
  PIN rx_payload[188]
    DIRECTION INPUT ;
    USE SIGNAL ;
    PORT
      LAYER M4 ;
        RECT  0 21.936 0.084 21.96 ;
    END
  END rx_payload[188]
  PIN rx_payload[189]
    DIRECTION INPUT ;
    USE SIGNAL ;
    PORT
      LAYER M4 ;
        RECT  0 22.032 0.084 22.056 ;
    END
  END rx_payload[189]
  PIN rx_payload[18]
    DIRECTION INPUT ;
    USE SIGNAL ;
    PORT
      LAYER M4 ;
        RECT  0 5.376 0.084 5.4 ;
    END
  END rx_payload[18]
  PIN rx_payload[190]
    DIRECTION INPUT ;
    USE SIGNAL ;
    PORT
      LAYER M4 ;
        RECT  0 22.128 0.084 22.152 ;
    END
  END rx_payload[190]
  PIN rx_payload[191]
    DIRECTION INPUT ;
    USE SIGNAL ;
    PORT
      LAYER M4 ;
        RECT  0 22.272 0.084 22.296 ;
    END
  END rx_payload[191]
  PIN rx_payload[192]
    DIRECTION INPUT ;
    USE SIGNAL ;
    PORT
      LAYER M4 ;
        RECT  0 22.368 0.084 22.392 ;
    END
  END rx_payload[192]
  PIN rx_payload[193]
    DIRECTION INPUT ;
    USE SIGNAL ;
    PORT
      LAYER M4 ;
        RECT  0 22.464 0.084 22.488 ;
    END
  END rx_payload[193]
  PIN rx_payload[194]
    DIRECTION INPUT ;
    USE SIGNAL ;
    PORT
      LAYER M4 ;
        RECT  0 22.56 0.084 22.584 ;
    END
  END rx_payload[194]
  PIN rx_payload[195]
    DIRECTION INPUT ;
    USE SIGNAL ;
    PORT
      LAYER M4 ;
        RECT  0 22.656 0.084 22.68 ;
    END
  END rx_payload[195]
  PIN rx_payload[196]
    DIRECTION INPUT ;
    USE SIGNAL ;
    PORT
      LAYER M4 ;
        RECT  0 22.752 0.084 22.776 ;
    END
  END rx_payload[196]
  PIN rx_payload[197]
    DIRECTION INPUT ;
    USE SIGNAL ;
    PORT
      LAYER M4 ;
        RECT  0 22.848 0.084 22.872 ;
    END
  END rx_payload[197]
  PIN rx_payload[198]
    DIRECTION INPUT ;
    USE SIGNAL ;
    PORT
      LAYER M4 ;
        RECT  0 22.944 0.084 22.968 ;
    END
  END rx_payload[198]
  PIN rx_payload[199]
    DIRECTION INPUT ;
    USE SIGNAL ;
    PORT
      LAYER M4 ;
        RECT  0 23.04 0.084 23.064 ;
    END
  END rx_payload[199]
  PIN rx_payload[19]
    DIRECTION INPUT ;
    USE SIGNAL ;
    PORT
      LAYER M4 ;
        RECT  0 5.472 0.084 5.496 ;
    END
  END rx_payload[19]
  PIN rx_payload[1]
    DIRECTION INPUT ;
    USE SIGNAL ;
    PORT
      LAYER M4 ;
        RECT  0 3.744 0.084 3.768 ;
    END
  END rx_payload[1]
  PIN rx_payload[200]
    DIRECTION INPUT ;
    USE SIGNAL ;
    PORT
      LAYER M4 ;
        RECT  0 23.136 0.084 23.16 ;
    END
  END rx_payload[200]
  PIN rx_payload[201]
    DIRECTION INPUT ;
    USE SIGNAL ;
    PORT
      LAYER M4 ;
        RECT  0 23.232 0.084 23.256 ;
    END
  END rx_payload[201]
  PIN rx_payload[202]
    DIRECTION INPUT ;
    USE SIGNAL ;
    PORT
      LAYER M4 ;
        RECT  0 23.328 0.084 23.352 ;
    END
  END rx_payload[202]
  PIN rx_payload[203]
    DIRECTION INPUT ;
    USE SIGNAL ;
    PORT
      LAYER M4 ;
        RECT  0 23.424 0.084 23.448 ;
    END
  END rx_payload[203]
  PIN rx_payload[204]
    DIRECTION INPUT ;
    USE SIGNAL ;
    PORT
      LAYER M4 ;
        RECT  0 23.52 0.084 23.544 ;
    END
  END rx_payload[204]
  PIN rx_payload[205]
    DIRECTION INPUT ;
    USE SIGNAL ;
    PORT
      LAYER M4 ;
        RECT  0 23.616 0.084 23.64 ;
    END
  END rx_payload[205]
  PIN rx_payload[206]
    DIRECTION INPUT ;
    USE SIGNAL ;
    PORT
      LAYER M4 ;
        RECT  0 23.712 0.084 23.736 ;
    END
  END rx_payload[206]
  PIN rx_payload[207]
    DIRECTION INPUT ;
    USE SIGNAL ;
    PORT
      LAYER M4 ;
        RECT  0 23.808 0.084 23.832 ;
    END
  END rx_payload[207]
  PIN rx_payload[208]
    DIRECTION INPUT ;
    USE SIGNAL ;
    PORT
      LAYER M4 ;
        RECT  0 23.904 0.084 23.928 ;
    END
  END rx_payload[208]
  PIN rx_payload[209]
    DIRECTION INPUT ;
    USE SIGNAL ;
    PORT
      LAYER M4 ;
        RECT  0 24 0.084 24.024 ;
    END
  END rx_payload[209]
  PIN rx_payload[20]
    DIRECTION INPUT ;
    USE SIGNAL ;
    PORT
      LAYER M4 ;
        RECT  0 5.568 0.084 5.592 ;
    END
  END rx_payload[20]
  PIN rx_payload[210]
    DIRECTION INPUT ;
    USE SIGNAL ;
    PORT
      LAYER M4 ;
        RECT  0 24.096 0.084 24.12 ;
    END
  END rx_payload[210]
  PIN rx_payload[211]
    DIRECTION INPUT ;
    USE SIGNAL ;
    PORT
      LAYER M4 ;
        RECT  0 24.192 0.084 24.216 ;
    END
  END rx_payload[211]
  PIN rx_payload[212]
    DIRECTION INPUT ;
    USE SIGNAL ;
    PORT
      LAYER M4 ;
        RECT  0 24.288 0.084 24.312 ;
    END
  END rx_payload[212]
  PIN rx_payload[213]
    DIRECTION INPUT ;
    USE SIGNAL ;
    PORT
      LAYER M4 ;
        RECT  0 24.384 0.084 24.408 ;
    END
  END rx_payload[213]
  PIN rx_payload[214]
    DIRECTION INPUT ;
    USE SIGNAL ;
    PORT
      LAYER M4 ;
        RECT  0 24.48 0.084 24.504 ;
    END
  END rx_payload[214]
  PIN rx_payload[215]
    DIRECTION INPUT ;
    USE SIGNAL ;
    PORT
      LAYER M4 ;
        RECT  0 24.576 0.084 24.6 ;
    END
  END rx_payload[215]
  PIN rx_payload[216]
    DIRECTION INPUT ;
    USE SIGNAL ;
    PORT
      LAYER M4 ;
        RECT  0 24.672 0.084 24.696 ;
    END
  END rx_payload[216]
  PIN rx_payload[217]
    DIRECTION INPUT ;
    USE SIGNAL ;
    PORT
      LAYER M4 ;
        RECT  0 24.768 0.084 24.792 ;
    END
  END rx_payload[217]
  PIN rx_payload[218]
    DIRECTION INPUT ;
    USE SIGNAL ;
    PORT
      LAYER M4 ;
        RECT  0 24.864 0.084 24.888 ;
    END
  END rx_payload[218]
  PIN rx_payload[219]
    DIRECTION INPUT ;
    USE SIGNAL ;
    PORT
      LAYER M4 ;
        RECT  0 24.96 0.084 24.984 ;
    END
  END rx_payload[219]
  PIN rx_payload[21]
    DIRECTION INPUT ;
    USE SIGNAL ;
    PORT
      LAYER M4 ;
        RECT  0 5.664 0.084 5.688 ;
    END
  END rx_payload[21]
  PIN rx_payload[220]
    DIRECTION INPUT ;
    USE SIGNAL ;
    PORT
      LAYER M4 ;
        RECT  0 25.056 0.084 25.08 ;
    END
  END rx_payload[220]
  PIN rx_payload[221]
    DIRECTION INPUT ;
    USE SIGNAL ;
    PORT
      LAYER M4 ;
        RECT  0 25.152 0.084 25.176 ;
    END
  END rx_payload[221]
  PIN rx_payload[222]
    DIRECTION INPUT ;
    USE SIGNAL ;
    PORT
      LAYER M4 ;
        RECT  0 25.248 0.084 25.272 ;
    END
  END rx_payload[222]
  PIN rx_payload[223]
    DIRECTION INPUT ;
    USE SIGNAL ;
    PORT
      LAYER M4 ;
        RECT  0 25.344 0.084 25.368 ;
    END
  END rx_payload[223]
  PIN rx_payload[224]
    DIRECTION INPUT ;
    USE SIGNAL ;
    PORT
      LAYER M4 ;
        RECT  0 25.488 0.084 25.512 ;
    END
  END rx_payload[224]
  PIN rx_payload[225]
    DIRECTION INPUT ;
    USE SIGNAL ;
    PORT
      LAYER M4 ;
        RECT  0 25.584 0.084 25.608 ;
    END
  END rx_payload[225]
  PIN rx_payload[226]
    DIRECTION INPUT ;
    USE SIGNAL ;
    PORT
      LAYER M4 ;
        RECT  0 25.68 0.084 25.704 ;
    END
  END rx_payload[226]
  PIN rx_payload[227]
    DIRECTION INPUT ;
    USE SIGNAL ;
    PORT
      LAYER M4 ;
        RECT  0 25.776 0.084 25.8 ;
    END
  END rx_payload[227]
  PIN rx_payload[228]
    DIRECTION INPUT ;
    USE SIGNAL ;
    PORT
      LAYER M4 ;
        RECT  0 25.872 0.084 25.896 ;
    END
  END rx_payload[228]
  PIN rx_payload[229]
    DIRECTION INPUT ;
    USE SIGNAL ;
    PORT
      LAYER M4 ;
        RECT  0 25.968 0.084 25.992 ;
    END
  END rx_payload[229]
  PIN rx_payload[22]
    DIRECTION INPUT ;
    USE SIGNAL ;
    PORT
      LAYER M4 ;
        RECT  0 5.76 0.084 5.784 ;
    END
  END rx_payload[22]
  PIN rx_payload[230]
    DIRECTION INPUT ;
    USE SIGNAL ;
    PORT
      LAYER M4 ;
        RECT  0 26.064 0.084 26.088 ;
    END
  END rx_payload[230]
  PIN rx_payload[231]
    DIRECTION INPUT ;
    USE SIGNAL ;
    PORT
      LAYER M4 ;
        RECT  0 26.16 0.084 26.184 ;
    END
  END rx_payload[231]
  PIN rx_payload[232]
    DIRECTION INPUT ;
    USE SIGNAL ;
    PORT
      LAYER M4 ;
        RECT  0 26.256 0.084 26.28 ;
    END
  END rx_payload[232]
  PIN rx_payload[233]
    DIRECTION INPUT ;
    USE SIGNAL ;
    PORT
      LAYER M4 ;
        RECT  0 26.352 0.084 26.376 ;
    END
  END rx_payload[233]
  PIN rx_payload[234]
    DIRECTION INPUT ;
    USE SIGNAL ;
    PORT
      LAYER M4 ;
        RECT  0 26.448 0.084 26.472 ;
    END
  END rx_payload[234]
  PIN rx_payload[235]
    DIRECTION INPUT ;
    USE SIGNAL ;
    PORT
      LAYER M4 ;
        RECT  0 26.544 0.084 26.568 ;
    END
  END rx_payload[235]
  PIN rx_payload[236]
    DIRECTION INPUT ;
    USE SIGNAL ;
    PORT
      LAYER M4 ;
        RECT  0 26.64 0.084 26.664 ;
    END
  END rx_payload[236]
  PIN rx_payload[237]
    DIRECTION INPUT ;
    USE SIGNAL ;
    PORT
      LAYER M4 ;
        RECT  0 26.736 0.084 26.76 ;
    END
  END rx_payload[237]
  PIN rx_payload[238]
    DIRECTION INPUT ;
    USE SIGNAL ;
    PORT
      LAYER M4 ;
        RECT  0 26.832 0.084 26.856 ;
    END
  END rx_payload[238]
  PIN rx_payload[239]
    DIRECTION INPUT ;
    USE SIGNAL ;
    PORT
      LAYER M4 ;
        RECT  0 26.928 0.084 26.952 ;
    END
  END rx_payload[239]
  PIN rx_payload[23]
    DIRECTION INPUT ;
    USE SIGNAL ;
    PORT
      LAYER M4 ;
        RECT  0 5.856 0.084 5.88 ;
    END
  END rx_payload[23]
  PIN rx_payload[240]
    DIRECTION INPUT ;
    USE SIGNAL ;
    PORT
      LAYER M4 ;
        RECT  0 27.024 0.084 27.048 ;
    END
  END rx_payload[240]
  PIN rx_payload[241]
    DIRECTION INPUT ;
    USE SIGNAL ;
    PORT
      LAYER M4 ;
        RECT  0 27.12 0.084 27.144 ;
    END
  END rx_payload[241]
  PIN rx_payload[242]
    DIRECTION INPUT ;
    USE SIGNAL ;
    PORT
      LAYER M4 ;
        RECT  0 27.216 0.084 27.24 ;
    END
  END rx_payload[242]
  PIN rx_payload[243]
    DIRECTION INPUT ;
    USE SIGNAL ;
    PORT
      LAYER M4 ;
        RECT  0 27.312 0.084 27.336 ;
    END
  END rx_payload[243]
  PIN rx_payload[244]
    DIRECTION INPUT ;
    USE SIGNAL ;
    PORT
      LAYER M4 ;
        RECT  0 27.408 0.084 27.432 ;
    END
  END rx_payload[244]
  PIN rx_payload[245]
    DIRECTION INPUT ;
    USE SIGNAL ;
    PORT
      LAYER M4 ;
        RECT  0 27.504 0.084 27.528 ;
    END
  END rx_payload[245]
  PIN rx_payload[246]
    DIRECTION INPUT ;
    USE SIGNAL ;
    PORT
      LAYER M4 ;
        RECT  0 27.6 0.084 27.624 ;
    END
  END rx_payload[246]
  PIN rx_payload[247]
    DIRECTION INPUT ;
    USE SIGNAL ;
    PORT
      LAYER M4 ;
        RECT  0 27.696 0.084 27.72 ;
    END
  END rx_payload[247]
  PIN rx_payload[248]
    DIRECTION INPUT ;
    USE SIGNAL ;
    PORT
      LAYER M4 ;
        RECT  0 27.792 0.084 27.816 ;
    END
  END rx_payload[248]
  PIN rx_payload[249]
    DIRECTION INPUT ;
    USE SIGNAL ;
    PORT
      LAYER M4 ;
        RECT  0 27.888 0.084 27.912 ;
    END
  END rx_payload[249]
  PIN rx_payload[24]
    DIRECTION INPUT ;
    USE SIGNAL ;
    PORT
      LAYER M4 ;
        RECT  0 5.952 0.084 5.976 ;
    END
  END rx_payload[24]
  PIN rx_payload[250]
    DIRECTION INPUT ;
    USE SIGNAL ;
    PORT
      LAYER M4 ;
        RECT  0 27.984 0.084 28.008 ;
    END
  END rx_payload[250]
  PIN rx_payload[251]
    DIRECTION INPUT ;
    USE SIGNAL ;
    PORT
      LAYER M4 ;
        RECT  0 28.08 0.084 28.104 ;
    END
  END rx_payload[251]
  PIN rx_payload[252]
    DIRECTION INPUT ;
    USE SIGNAL ;
    PORT
      LAYER M4 ;
        RECT  0 28.176 0.084 28.2 ;
    END
  END rx_payload[252]
  PIN rx_payload[253]
    DIRECTION INPUT ;
    USE SIGNAL ;
    PORT
      LAYER M4 ;
        RECT  0 28.272 0.084 28.296 ;
    END
  END rx_payload[253]
  PIN rx_payload[254]
    DIRECTION INPUT ;
    USE SIGNAL ;
    PORT
      LAYER M4 ;
        RECT  0 28.368 0.084 28.392 ;
    END
  END rx_payload[254]
  PIN rx_payload[255]
    DIRECTION INPUT ;
    USE SIGNAL ;
    PORT
      LAYER M4 ;
        RECT  0 28.464 0.084 28.488 ;
    END
  END rx_payload[255]
  PIN rx_payload[256]
    DIRECTION INPUT ;
    USE SIGNAL ;
    PORT
      LAYER M4 ;
        RECT  0 28.56 0.084 28.584 ;
    END
  END rx_payload[256]
  PIN rx_payload[257]
    DIRECTION INPUT ;
    USE SIGNAL ;
    PORT
      LAYER M4 ;
        RECT  0 28.704 0.084 28.728 ;
    END
  END rx_payload[257]
  PIN rx_payload[258]
    DIRECTION INPUT ;
    USE SIGNAL ;
    PORT
      LAYER M4 ;
        RECT  0 28.8 0.084 28.824 ;
    END
  END rx_payload[258]
  PIN rx_payload[259]
    DIRECTION INPUT ;
    USE SIGNAL ;
    PORT
      LAYER M4 ;
        RECT  0 28.896 0.084 28.92 ;
    END
  END rx_payload[259]
  PIN rx_payload[25]
    DIRECTION INPUT ;
    USE SIGNAL ;
    PORT
      LAYER M4 ;
        RECT  0 6.096 0.084 6.12 ;
    END
  END rx_payload[25]
  PIN rx_payload[260]
    DIRECTION INPUT ;
    USE SIGNAL ;
    PORT
      LAYER M4 ;
        RECT  0 28.992 0.084 29.016 ;
    END
  END rx_payload[260]
  PIN rx_payload[261]
    DIRECTION INPUT ;
    USE SIGNAL ;
    PORT
      LAYER M4 ;
        RECT  0 29.088 0.084 29.112 ;
    END
  END rx_payload[261]
  PIN rx_payload[262]
    DIRECTION INPUT ;
    USE SIGNAL ;
    PORT
      LAYER M4 ;
        RECT  0 29.184 0.084 29.208 ;
    END
  END rx_payload[262]
  PIN rx_payload[263]
    DIRECTION INPUT ;
    USE SIGNAL ;
    PORT
      LAYER M4 ;
        RECT  0 29.28 0.084 29.304 ;
    END
  END rx_payload[263]
  PIN rx_payload[264]
    DIRECTION INPUT ;
    USE SIGNAL ;
    PORT
      LAYER M4 ;
        RECT  0 29.376 0.084 29.4 ;
    END
  END rx_payload[264]
  PIN rx_payload[265]
    DIRECTION INPUT ;
    USE SIGNAL ;
    PORT
      LAYER M4 ;
        RECT  0 29.472 0.084 29.496 ;
    END
  END rx_payload[265]
  PIN rx_payload[266]
    DIRECTION INPUT ;
    USE SIGNAL ;
    PORT
      LAYER M4 ;
        RECT  0 29.568 0.084 29.592 ;
    END
  END rx_payload[266]
  PIN rx_payload[267]
    DIRECTION INPUT ;
    USE SIGNAL ;
    PORT
      LAYER M4 ;
        RECT  0 29.664 0.084 29.688 ;
    END
  END rx_payload[267]
  PIN rx_payload[268]
    DIRECTION INPUT ;
    USE SIGNAL ;
    PORT
      LAYER M4 ;
        RECT  0 29.76 0.084 29.784 ;
    END
  END rx_payload[268]
  PIN rx_payload[269]
    DIRECTION INPUT ;
    USE SIGNAL ;
    PORT
      LAYER M4 ;
        RECT  0 29.856 0.084 29.88 ;
    END
  END rx_payload[269]
  PIN rx_payload[26]
    DIRECTION INPUT ;
    USE SIGNAL ;
    PORT
      LAYER M4 ;
        RECT  0 6.192 0.084 6.216 ;
    END
  END rx_payload[26]
  PIN rx_payload[270]
    DIRECTION INPUT ;
    USE SIGNAL ;
    PORT
      LAYER M4 ;
        RECT  0 29.952 0.084 29.976 ;
    END
  END rx_payload[270]
  PIN rx_payload[271]
    DIRECTION INPUT ;
    USE SIGNAL ;
    PORT
      LAYER M4 ;
        RECT  0 30.048 0.084 30.072 ;
    END
  END rx_payload[271]
  PIN rx_payload[272]
    DIRECTION INPUT ;
    USE SIGNAL ;
    PORT
      LAYER M4 ;
        RECT  0 30.144 0.084 30.168 ;
    END
  END rx_payload[272]
  PIN rx_payload[273]
    DIRECTION INPUT ;
    USE SIGNAL ;
    PORT
      LAYER M4 ;
        RECT  0 30.24 0.084 30.264 ;
    END
  END rx_payload[273]
  PIN rx_payload[274]
    DIRECTION INPUT ;
    USE SIGNAL ;
    PORT
      LAYER M4 ;
        RECT  0 30.336 0.084 30.36 ;
    END
  END rx_payload[274]
  PIN rx_payload[275]
    DIRECTION INPUT ;
    USE SIGNAL ;
    PORT
      LAYER M4 ;
        RECT  0 30.432 0.084 30.456 ;
    END
  END rx_payload[275]
  PIN rx_payload[276]
    DIRECTION INPUT ;
    USE SIGNAL ;
    PORT
      LAYER M4 ;
        RECT  0 30.528 0.084 30.552 ;
    END
  END rx_payload[276]
  PIN rx_payload[277]
    DIRECTION INPUT ;
    USE SIGNAL ;
    PORT
      LAYER M4 ;
        RECT  0 30.624 0.084 30.648 ;
    END
  END rx_payload[277]
  PIN rx_payload[278]
    DIRECTION INPUT ;
    USE SIGNAL ;
    PORT
      LAYER M4 ;
        RECT  0 30.72 0.084 30.744 ;
    END
  END rx_payload[278]
  PIN rx_payload[279]
    DIRECTION INPUT ;
    USE SIGNAL ;
    PORT
      LAYER M4 ;
        RECT  0 30.816 0.084 30.84 ;
    END
  END rx_payload[279]
  PIN rx_payload[27]
    DIRECTION INPUT ;
    USE SIGNAL ;
    PORT
      LAYER M4 ;
        RECT  0 6.288 0.084 6.312 ;
    END
  END rx_payload[27]
  PIN rx_payload[280]
    DIRECTION INPUT ;
    USE SIGNAL ;
    PORT
      LAYER M4 ;
        RECT  0 30.912 0.084 30.936 ;
    END
  END rx_payload[280]
  PIN rx_payload[281]
    DIRECTION INPUT ;
    USE SIGNAL ;
    PORT
      LAYER M4 ;
        RECT  0 31.008 0.084 31.032 ;
    END
  END rx_payload[281]
  PIN rx_payload[282]
    DIRECTION INPUT ;
    USE SIGNAL ;
    PORT
      LAYER M4 ;
        RECT  0 31.104 0.084 31.128 ;
    END
  END rx_payload[282]
  PIN rx_payload[283]
    DIRECTION INPUT ;
    USE SIGNAL ;
    PORT
      LAYER M4 ;
        RECT  0 31.2 0.084 31.224 ;
    END
  END rx_payload[283]
  PIN rx_payload[284]
    DIRECTION INPUT ;
    USE SIGNAL ;
    PORT
      LAYER M4 ;
        RECT  0 31.296 0.084 31.32 ;
    END
  END rx_payload[284]
  PIN rx_payload[285]
    DIRECTION INPUT ;
    USE SIGNAL ;
    PORT
      LAYER M4 ;
        RECT  0 31.392 0.084 31.416 ;
    END
  END rx_payload[285]
  PIN rx_payload[286]
    DIRECTION INPUT ;
    USE SIGNAL ;
    PORT
      LAYER M4 ;
        RECT  0 31.488 0.084 31.512 ;
    END
  END rx_payload[286]
  PIN rx_payload[287]
    DIRECTION INPUT ;
    USE SIGNAL ;
    PORT
      LAYER M4 ;
        RECT  0 31.584 0.084 31.608 ;
    END
  END rx_payload[287]
  PIN rx_payload[288]
    DIRECTION INPUT ;
    USE SIGNAL ;
    PORT
      LAYER M4 ;
        RECT  0 31.68 0.084 31.704 ;
    END
  END rx_payload[288]
  PIN rx_payload[289]
    DIRECTION INPUT ;
    USE SIGNAL ;
    PORT
      LAYER M4 ;
        RECT  0 31.776 0.084 31.8 ;
    END
  END rx_payload[289]
  PIN rx_payload[28]
    DIRECTION INPUT ;
    USE SIGNAL ;
    PORT
      LAYER M4 ;
        RECT  0 6.384 0.084 6.408 ;
    END
  END rx_payload[28]
  PIN rx_payload[290]
    DIRECTION INPUT ;
    USE SIGNAL ;
    PORT
      LAYER M4 ;
        RECT  0 31.92 0.084 31.944 ;
    END
  END rx_payload[290]
  PIN rx_payload[291]
    DIRECTION INPUT ;
    USE SIGNAL ;
    PORT
      LAYER M4 ;
        RECT  0 32.016 0.084 32.04 ;
    END
  END rx_payload[291]
  PIN rx_payload[292]
    DIRECTION INPUT ;
    USE SIGNAL ;
    PORT
      LAYER M4 ;
        RECT  0 32.112 0.084 32.136 ;
    END
  END rx_payload[292]
  PIN rx_payload[293]
    DIRECTION INPUT ;
    USE SIGNAL ;
    PORT
      LAYER M4 ;
        RECT  0 32.208 0.084 32.232 ;
    END
  END rx_payload[293]
  PIN rx_payload[294]
    DIRECTION INPUT ;
    USE SIGNAL ;
    PORT
      LAYER M4 ;
        RECT  0 32.304 0.084 32.328 ;
    END
  END rx_payload[294]
  PIN rx_payload[295]
    DIRECTION INPUT ;
    USE SIGNAL ;
    PORT
      LAYER M4 ;
        RECT  0 32.4 0.084 32.424 ;
    END
  END rx_payload[295]
  PIN rx_payload[296]
    DIRECTION INPUT ;
    USE SIGNAL ;
    PORT
      LAYER M4 ;
        RECT  0 32.496 0.084 32.52 ;
    END
  END rx_payload[296]
  PIN rx_payload[297]
    DIRECTION INPUT ;
    USE SIGNAL ;
    PORT
      LAYER M4 ;
        RECT  0 32.592 0.084 32.616 ;
    END
  END rx_payload[297]
  PIN rx_payload[298]
    DIRECTION INPUT ;
    USE SIGNAL ;
    PORT
      LAYER M4 ;
        RECT  0 32.688 0.084 32.712 ;
    END
  END rx_payload[298]
  PIN rx_payload[299]
    DIRECTION INPUT ;
    USE SIGNAL ;
    PORT
      LAYER M4 ;
        RECT  0 32.784 0.084 32.808 ;
    END
  END rx_payload[299]
  PIN rx_payload[29]
    DIRECTION INPUT ;
    USE SIGNAL ;
    PORT
      LAYER M4 ;
        RECT  0 6.48 0.084 6.504 ;
    END
  END rx_payload[29]
  PIN rx_payload[2]
    DIRECTION INPUT ;
    USE SIGNAL ;
    PORT
      LAYER M4 ;
        RECT  0 3.84 0.084 3.864 ;
    END
  END rx_payload[2]
  PIN rx_payload[300]
    DIRECTION INPUT ;
    USE SIGNAL ;
    PORT
      LAYER M4 ;
        RECT  0 32.88 0.084 32.904 ;
    END
  END rx_payload[300]
  PIN rx_payload[301]
    DIRECTION INPUT ;
    USE SIGNAL ;
    PORT
      LAYER M4 ;
        RECT  0 32.976 0.084 33 ;
    END
  END rx_payload[301]
  PIN rx_payload[302]
    DIRECTION INPUT ;
    USE SIGNAL ;
    PORT
      LAYER M4 ;
        RECT  0 33.072 0.084 33.096 ;
    END
  END rx_payload[302]
  PIN rx_payload[303]
    DIRECTION INPUT ;
    USE SIGNAL ;
    PORT
      LAYER M4 ;
        RECT  0 33.168 0.084 33.192 ;
    END
  END rx_payload[303]
  PIN rx_payload[304]
    DIRECTION INPUT ;
    USE SIGNAL ;
    PORT
      LAYER M4 ;
        RECT  0 33.264 0.084 33.288 ;
    END
  END rx_payload[304]
  PIN rx_payload[305]
    DIRECTION INPUT ;
    USE SIGNAL ;
    PORT
      LAYER M4 ;
        RECT  0 33.36 0.084 33.384 ;
    END
  END rx_payload[305]
  PIN rx_payload[306]
    DIRECTION INPUT ;
    USE SIGNAL ;
    PORT
      LAYER M4 ;
        RECT  0 33.456 0.084 33.48 ;
    END
  END rx_payload[306]
  PIN rx_payload[307]
    DIRECTION INPUT ;
    USE SIGNAL ;
    PORT
      LAYER M4 ;
        RECT  0 33.552 0.084 33.576 ;
    END
  END rx_payload[307]
  PIN rx_payload[308]
    DIRECTION INPUT ;
    USE SIGNAL ;
    PORT
      LAYER M4 ;
        RECT  0 33.648 0.084 33.672 ;
    END
  END rx_payload[308]
  PIN rx_payload[309]
    DIRECTION INPUT ;
    USE SIGNAL ;
    PORT
      LAYER M4 ;
        RECT  0 33.744 0.084 33.768 ;
    END
  END rx_payload[309]
  PIN rx_payload[30]
    DIRECTION INPUT ;
    USE SIGNAL ;
    PORT
      LAYER M4 ;
        RECT  0 6.576 0.084 6.6 ;
    END
  END rx_payload[30]
  PIN rx_payload[310]
    DIRECTION INPUT ;
    USE SIGNAL ;
    PORT
      LAYER M4 ;
        RECT  0 33.84 0.084 33.864 ;
    END
  END rx_payload[310]
  PIN rx_payload[311]
    DIRECTION INPUT ;
    USE SIGNAL ;
    PORT
      LAYER M4 ;
        RECT  0 33.936 0.084 33.96 ;
    END
  END rx_payload[311]
  PIN rx_payload[312]
    DIRECTION INPUT ;
    USE SIGNAL ;
    PORT
      LAYER M4 ;
        RECT  0 34.032 0.084 34.056 ;
    END
  END rx_payload[312]
  PIN rx_payload[313]
    DIRECTION INPUT ;
    USE SIGNAL ;
    PORT
      LAYER M4 ;
        RECT  0 34.128 0.084 34.152 ;
    END
  END rx_payload[313]
  PIN rx_payload[314]
    DIRECTION INPUT ;
    USE SIGNAL ;
    PORT
      LAYER M4 ;
        RECT  0 34.224 0.084 34.248 ;
    END
  END rx_payload[314]
  PIN rx_payload[315]
    DIRECTION INPUT ;
    USE SIGNAL ;
    PORT
      LAYER M4 ;
        RECT  0 34.32 0.084 34.344 ;
    END
  END rx_payload[315]
  PIN rx_payload[316]
    DIRECTION INPUT ;
    USE SIGNAL ;
    PORT
      LAYER M4 ;
        RECT  0 34.416 0.084 34.44 ;
    END
  END rx_payload[316]
  PIN rx_payload[317]
    DIRECTION INPUT ;
    USE SIGNAL ;
    PORT
      LAYER M4 ;
        RECT  0 34.512 0.084 34.536 ;
    END
  END rx_payload[317]
  PIN rx_payload[318]
    DIRECTION INPUT ;
    USE SIGNAL ;
    PORT
      LAYER M4 ;
        RECT  0 34.608 0.084 34.632 ;
    END
  END rx_payload[318]
  PIN rx_payload[319]
    DIRECTION INPUT ;
    USE SIGNAL ;
    PORT
      LAYER M4 ;
        RECT  0 34.704 0.084 34.728 ;
    END
  END rx_payload[319]
  PIN rx_payload[31]
    DIRECTION INPUT ;
    USE SIGNAL ;
    PORT
      LAYER M4 ;
        RECT  0 6.672 0.084 6.696 ;
    END
  END rx_payload[31]
  PIN rx_payload[320]
    DIRECTION INPUT ;
    USE SIGNAL ;
    PORT
      LAYER M4 ;
        RECT  0 34.8 0.084 34.824 ;
    END
  END rx_payload[320]
  PIN rx_payload[321]
    DIRECTION INPUT ;
    USE SIGNAL ;
    PORT
      LAYER M4 ;
        RECT  0 34.896 0.084 34.92 ;
    END
  END rx_payload[321]
  PIN rx_payload[322]
    DIRECTION INPUT ;
    USE SIGNAL ;
    PORT
      LAYER M4 ;
        RECT  0 34.992 0.084 35.016 ;
    END
  END rx_payload[322]
  PIN rx_payload[323]
    DIRECTION INPUT ;
    USE SIGNAL ;
    PORT
      LAYER M4 ;
        RECT  0 35.136 0.084 35.16 ;
    END
  END rx_payload[323]
  PIN rx_payload[324]
    DIRECTION INPUT ;
    USE SIGNAL ;
    PORT
      LAYER M4 ;
        RECT  0 35.232 0.084 35.256 ;
    END
  END rx_payload[324]
  PIN rx_payload[325]
    DIRECTION INPUT ;
    USE SIGNAL ;
    PORT
      LAYER M4 ;
        RECT  0 35.328 0.084 35.352 ;
    END
  END rx_payload[325]
  PIN rx_payload[326]
    DIRECTION INPUT ;
    USE SIGNAL ;
    PORT
      LAYER M4 ;
        RECT  0 35.424 0.084 35.448 ;
    END
  END rx_payload[326]
  PIN rx_payload[327]
    DIRECTION INPUT ;
    USE SIGNAL ;
    PORT
      LAYER M4 ;
        RECT  0 35.52 0.084 35.544 ;
    END
  END rx_payload[327]
  PIN rx_payload[328]
    DIRECTION INPUT ;
    USE SIGNAL ;
    PORT
      LAYER M4 ;
        RECT  0 35.616 0.084 35.64 ;
    END
  END rx_payload[328]
  PIN rx_payload[329]
    DIRECTION INPUT ;
    USE SIGNAL ;
    PORT
      LAYER M4 ;
        RECT  0 35.712 0.084 35.736 ;
    END
  END rx_payload[329]
  PIN rx_payload[32]
    DIRECTION INPUT ;
    USE SIGNAL ;
    PORT
      LAYER M4 ;
        RECT  0 6.768 0.084 6.792 ;
    END
  END rx_payload[32]
  PIN rx_payload[330]
    DIRECTION INPUT ;
    USE SIGNAL ;
    PORT
      LAYER M4 ;
        RECT  0 35.808 0.084 35.832 ;
    END
  END rx_payload[330]
  PIN rx_payload[331]
    DIRECTION INPUT ;
    USE SIGNAL ;
    PORT
      LAYER M4 ;
        RECT  0 35.904 0.084 35.928 ;
    END
  END rx_payload[331]
  PIN rx_payload[332]
    DIRECTION INPUT ;
    USE SIGNAL ;
    PORT
      LAYER M4 ;
        RECT  0 36 0.084 36.024 ;
    END
  END rx_payload[332]
  PIN rx_payload[333]
    DIRECTION INPUT ;
    USE SIGNAL ;
    PORT
      LAYER M4 ;
        RECT  0 36.096 0.084 36.12 ;
    END
  END rx_payload[333]
  PIN rx_payload[334]
    DIRECTION INPUT ;
    USE SIGNAL ;
    PORT
      LAYER M4 ;
        RECT  0 36.192 0.084 36.216 ;
    END
  END rx_payload[334]
  PIN rx_payload[335]
    DIRECTION INPUT ;
    USE SIGNAL ;
    PORT
      LAYER M4 ;
        RECT  0 36.288 0.084 36.312 ;
    END
  END rx_payload[335]
  PIN rx_payload[336]
    DIRECTION INPUT ;
    USE SIGNAL ;
    PORT
      LAYER M4 ;
        RECT  0 36.384 0.084 36.408 ;
    END
  END rx_payload[336]
  PIN rx_payload[337]
    DIRECTION INPUT ;
    USE SIGNAL ;
    PORT
      LAYER M4 ;
        RECT  0 36.48 0.084 36.504 ;
    END
  END rx_payload[337]
  PIN rx_payload[338]
    DIRECTION INPUT ;
    USE SIGNAL ;
    PORT
      LAYER M4 ;
        RECT  0 36.576 0.084 36.6 ;
    END
  END rx_payload[338]
  PIN rx_payload[339]
    DIRECTION INPUT ;
    USE SIGNAL ;
    PORT
      LAYER M4 ;
        RECT  0 36.672 0.084 36.696 ;
    END
  END rx_payload[339]
  PIN rx_payload[33]
    DIRECTION INPUT ;
    USE SIGNAL ;
    PORT
      LAYER M4 ;
        RECT  0 6.864 0.084 6.888 ;
    END
  END rx_payload[33]
  PIN rx_payload[340]
    DIRECTION INPUT ;
    USE SIGNAL ;
    PORT
      LAYER M4 ;
        RECT  0 36.768 0.084 36.792 ;
    END
  END rx_payload[340]
  PIN rx_payload[341]
    DIRECTION INPUT ;
    USE SIGNAL ;
    PORT
      LAYER M4 ;
        RECT  0 36.864 0.084 36.888 ;
    END
  END rx_payload[341]
  PIN rx_payload[342]
    DIRECTION INPUT ;
    USE SIGNAL ;
    PORT
      LAYER M4 ;
        RECT  0 36.96 0.084 36.984 ;
    END
  END rx_payload[342]
  PIN rx_payload[343]
    DIRECTION INPUT ;
    USE SIGNAL ;
    PORT
      LAYER M4 ;
        RECT  0 37.056 0.084 37.08 ;
    END
  END rx_payload[343]
  PIN rx_payload[344]
    DIRECTION INPUT ;
    USE SIGNAL ;
    PORT
      LAYER M4 ;
        RECT  0 37.152 0.084 37.176 ;
    END
  END rx_payload[344]
  PIN rx_payload[345]
    DIRECTION INPUT ;
    USE SIGNAL ;
    PORT
      LAYER M4 ;
        RECT  0 37.248 0.084 37.272 ;
    END
  END rx_payload[345]
  PIN rx_payload[346]
    DIRECTION INPUT ;
    USE SIGNAL ;
    PORT
      LAYER M4 ;
        RECT  0 37.344 0.084 37.368 ;
    END
  END rx_payload[346]
  PIN rx_payload[347]
    DIRECTION INPUT ;
    USE SIGNAL ;
    PORT
      LAYER M4 ;
        RECT  0 37.44 0.084 37.464 ;
    END
  END rx_payload[347]
  PIN rx_payload[348]
    DIRECTION INPUT ;
    USE SIGNAL ;
    PORT
      LAYER M4 ;
        RECT  0 37.536 0.084 37.56 ;
    END
  END rx_payload[348]
  PIN rx_payload[349]
    DIRECTION INPUT ;
    USE SIGNAL ;
    PORT
      LAYER M4 ;
        RECT  0 37.632 0.084 37.656 ;
    END
  END rx_payload[349]
  PIN rx_payload[34]
    DIRECTION INPUT ;
    USE SIGNAL ;
    PORT
      LAYER M4 ;
        RECT  0 6.96 0.084 6.984 ;
    END
  END rx_payload[34]
  PIN rx_payload[350]
    DIRECTION INPUT ;
    USE SIGNAL ;
    PORT
      LAYER M4 ;
        RECT  0 37.728 0.084 37.752 ;
    END
  END rx_payload[350]
  PIN rx_payload[351]
    DIRECTION INPUT ;
    USE SIGNAL ;
    PORT
      LAYER M4 ;
        RECT  0 37.824 0.084 37.848 ;
    END
  END rx_payload[351]
  PIN rx_payload[352]
    DIRECTION INPUT ;
    USE SIGNAL ;
    PORT
      LAYER M4 ;
        RECT  0 37.92 0.084 37.944 ;
    END
  END rx_payload[352]
  PIN rx_payload[353]
    DIRECTION INPUT ;
    USE SIGNAL ;
    PORT
      LAYER M4 ;
        RECT  0 38.016 0.084 38.04 ;
    END
  END rx_payload[353]
  PIN rx_payload[354]
    DIRECTION INPUT ;
    USE SIGNAL ;
    PORT
      LAYER M4 ;
        RECT  0 38.112 0.084 38.136 ;
    END
  END rx_payload[354]
  PIN rx_payload[355]
    DIRECTION INPUT ;
    USE SIGNAL ;
    PORT
      LAYER M4 ;
        RECT  0 38.208 0.084 38.232 ;
    END
  END rx_payload[355]
  PIN rx_payload[356]
    DIRECTION INPUT ;
    USE SIGNAL ;
    PORT
      LAYER M4 ;
        RECT  0 38.304 0.084 38.328 ;
    END
  END rx_payload[356]
  PIN rx_payload[357]
    DIRECTION INPUT ;
    USE SIGNAL ;
    PORT
      LAYER M4 ;
        RECT  0 38.448 0.084 38.472 ;
    END
  END rx_payload[357]
  PIN rx_payload[358]
    DIRECTION INPUT ;
    USE SIGNAL ;
    PORT
      LAYER M4 ;
        RECT  0 38.544 0.084 38.568 ;
    END
  END rx_payload[358]
  PIN rx_payload[359]
    DIRECTION INPUT ;
    USE SIGNAL ;
    PORT
      LAYER M4 ;
        RECT  0 38.64 0.084 38.664 ;
    END
  END rx_payload[359]
  PIN rx_payload[35]
    DIRECTION INPUT ;
    USE SIGNAL ;
    PORT
      LAYER M4 ;
        RECT  0 7.056 0.084 7.08 ;
    END
  END rx_payload[35]
  PIN rx_payload[360]
    DIRECTION INPUT ;
    USE SIGNAL ;
    PORT
      LAYER M4 ;
        RECT  0 38.736 0.084 38.76 ;
    END
  END rx_payload[360]
  PIN rx_payload[361]
    DIRECTION INPUT ;
    USE SIGNAL ;
    PORT
      LAYER M4 ;
        RECT  0 38.832 0.084 38.856 ;
    END
  END rx_payload[361]
  PIN rx_payload[362]
    DIRECTION INPUT ;
    USE SIGNAL ;
    PORT
      LAYER M4 ;
        RECT  0 38.928 0.084 38.952 ;
    END
  END rx_payload[362]
  PIN rx_payload[363]
    DIRECTION INPUT ;
    USE SIGNAL ;
    PORT
      LAYER M4 ;
        RECT  0 39.024 0.084 39.048 ;
    END
  END rx_payload[363]
  PIN rx_payload[364]
    DIRECTION INPUT ;
    USE SIGNAL ;
    PORT
      LAYER M4 ;
        RECT  0 39.12 0.084 39.144 ;
    END
  END rx_payload[364]
  PIN rx_payload[365]
    DIRECTION INPUT ;
    USE SIGNAL ;
    PORT
      LAYER M4 ;
        RECT  0 39.216 0.084 39.24 ;
    END
  END rx_payload[365]
  PIN rx_payload[366]
    DIRECTION INPUT ;
    USE SIGNAL ;
    PORT
      LAYER M4 ;
        RECT  0 39.312 0.084 39.336 ;
    END
  END rx_payload[366]
  PIN rx_payload[367]
    DIRECTION INPUT ;
    USE SIGNAL ;
    PORT
      LAYER M4 ;
        RECT  0 39.408 0.084 39.432 ;
    END
  END rx_payload[367]
  PIN rx_payload[368]
    DIRECTION INPUT ;
    USE SIGNAL ;
    PORT
      LAYER M4 ;
        RECT  0 39.504 0.084 39.528 ;
    END
  END rx_payload[368]
  PIN rx_payload[369]
    DIRECTION INPUT ;
    USE SIGNAL ;
    PORT
      LAYER M4 ;
        RECT  0 39.6 0.084 39.624 ;
    END
  END rx_payload[369]
  PIN rx_payload[36]
    DIRECTION INPUT ;
    USE SIGNAL ;
    PORT
      LAYER M4 ;
        RECT  0 7.152 0.084 7.176 ;
    END
  END rx_payload[36]
  PIN rx_payload[370]
    DIRECTION INPUT ;
    USE SIGNAL ;
    PORT
      LAYER M4 ;
        RECT  0 39.696 0.084 39.72 ;
    END
  END rx_payload[370]
  PIN rx_payload[371]
    DIRECTION INPUT ;
    USE SIGNAL ;
    PORT
      LAYER M4 ;
        RECT  0 39.792 0.084 39.816 ;
    END
  END rx_payload[371]
  PIN rx_payload[372]
    DIRECTION INPUT ;
    USE SIGNAL ;
    PORT
      LAYER M4 ;
        RECT  0 39.888 0.084 39.912 ;
    END
  END rx_payload[372]
  PIN rx_payload[373]
    DIRECTION INPUT ;
    USE SIGNAL ;
    PORT
      LAYER M4 ;
        RECT  0 39.984 0.084 40.008 ;
    END
  END rx_payload[373]
  PIN rx_payload[374]
    DIRECTION INPUT ;
    USE SIGNAL ;
    PORT
      LAYER M4 ;
        RECT  0 40.08 0.084 40.104 ;
    END
  END rx_payload[374]
  PIN rx_payload[375]
    DIRECTION INPUT ;
    USE SIGNAL ;
    PORT
      LAYER M4 ;
        RECT  0 40.176 0.084 40.2 ;
    END
  END rx_payload[375]
  PIN rx_payload[376]
    DIRECTION INPUT ;
    USE SIGNAL ;
    PORT
      LAYER M4 ;
        RECT  0 40.272 0.084 40.296 ;
    END
  END rx_payload[376]
  PIN rx_payload[377]
    DIRECTION INPUT ;
    USE SIGNAL ;
    PORT
      LAYER M4 ;
        RECT  0 40.368 0.084 40.392 ;
    END
  END rx_payload[377]
  PIN rx_payload[378]
    DIRECTION INPUT ;
    USE SIGNAL ;
    PORT
      LAYER M4 ;
        RECT  0 40.464 0.084 40.488 ;
    END
  END rx_payload[378]
  PIN rx_payload[379]
    DIRECTION INPUT ;
    USE SIGNAL ;
    PORT
      LAYER M4 ;
        RECT  0 40.56 0.084 40.584 ;
    END
  END rx_payload[379]
  PIN rx_payload[37]
    DIRECTION INPUT ;
    USE SIGNAL ;
    PORT
      LAYER M4 ;
        RECT  0 7.248 0.084 7.272 ;
    END
  END rx_payload[37]
  PIN rx_payload[380]
    DIRECTION INPUT ;
    USE SIGNAL ;
    PORT
      LAYER M4 ;
        RECT  0 40.656 0.084 40.68 ;
    END
  END rx_payload[380]
  PIN rx_payload[381]
    DIRECTION INPUT ;
    USE SIGNAL ;
    PORT
      LAYER M4 ;
        RECT  0 40.752 0.084 40.776 ;
    END
  END rx_payload[381]
  PIN rx_payload[382]
    DIRECTION INPUT ;
    USE SIGNAL ;
    PORT
      LAYER M4 ;
        RECT  0 40.848 0.084 40.872 ;
    END
  END rx_payload[382]
  PIN rx_payload[383]
    DIRECTION INPUT ;
    USE SIGNAL ;
    PORT
      LAYER M4 ;
        RECT  0 40.944 0.084 40.968 ;
    END
  END rx_payload[383]
  PIN rx_payload[384]
    DIRECTION INPUT ;
    USE SIGNAL ;
    PORT
      LAYER M4 ;
        RECT  0 41.04 0.084 41.064 ;
    END
  END rx_payload[384]
  PIN rx_payload[385]
    DIRECTION INPUT ;
    USE SIGNAL ;
    PORT
      LAYER M4 ;
        RECT  0 41.136 0.084 41.16 ;
    END
  END rx_payload[385]
  PIN rx_payload[386]
    DIRECTION INPUT ;
    USE SIGNAL ;
    PORT
      LAYER M4 ;
        RECT  0 41.232 0.084 41.256 ;
    END
  END rx_payload[386]
  PIN rx_payload[387]
    DIRECTION INPUT ;
    USE SIGNAL ;
    PORT
      LAYER M4 ;
        RECT  0 41.328 0.084 41.352 ;
    END
  END rx_payload[387]
  PIN rx_payload[388]
    DIRECTION INPUT ;
    USE SIGNAL ;
    PORT
      LAYER M4 ;
        RECT  0 41.424 0.084 41.448 ;
    END
  END rx_payload[388]
  PIN rx_payload[389]
    DIRECTION INPUT ;
    USE SIGNAL ;
    PORT
      LAYER M4 ;
        RECT  0 41.52 0.084 41.544 ;
    END
  END rx_payload[389]
  PIN rx_payload[38]
    DIRECTION INPUT ;
    USE SIGNAL ;
    PORT
      LAYER M4 ;
        RECT  0 7.344 0.084 7.368 ;
    END
  END rx_payload[38]
  PIN rx_payload[390]
    DIRECTION INPUT ;
    USE SIGNAL ;
    PORT
      LAYER M4 ;
        RECT  0 41.664 0.084 41.688 ;
    END
  END rx_payload[390]
  PIN rx_payload[391]
    DIRECTION INPUT ;
    USE SIGNAL ;
    PORT
      LAYER M4 ;
        RECT  0 41.76 0.084 41.784 ;
    END
  END rx_payload[391]
  PIN rx_payload[392]
    DIRECTION INPUT ;
    USE SIGNAL ;
    PORT
      LAYER M4 ;
        RECT  0 41.856 0.084 41.88 ;
    END
  END rx_payload[392]
  PIN rx_payload[393]
    DIRECTION INPUT ;
    USE SIGNAL ;
    PORT
      LAYER M4 ;
        RECT  0 41.952 0.084 41.976 ;
    END
  END rx_payload[393]
  PIN rx_payload[394]
    DIRECTION INPUT ;
    USE SIGNAL ;
    PORT
      LAYER M4 ;
        RECT  0 42.048 0.084 42.072 ;
    END
  END rx_payload[394]
  PIN rx_payload[395]
    DIRECTION INPUT ;
    USE SIGNAL ;
    PORT
      LAYER M4 ;
        RECT  0 42.144 0.084 42.168 ;
    END
  END rx_payload[395]
  PIN rx_payload[396]
    DIRECTION INPUT ;
    USE SIGNAL ;
    PORT
      LAYER M4 ;
        RECT  0 42.24 0.084 42.264 ;
    END
  END rx_payload[396]
  PIN rx_payload[397]
    DIRECTION INPUT ;
    USE SIGNAL ;
    PORT
      LAYER M4 ;
        RECT  0 42.336 0.084 42.36 ;
    END
  END rx_payload[397]
  PIN rx_payload[398]
    DIRECTION INPUT ;
    USE SIGNAL ;
    PORT
      LAYER M4 ;
        RECT  0 42.432 0.084 42.456 ;
    END
  END rx_payload[398]
  PIN rx_payload[399]
    DIRECTION INPUT ;
    USE SIGNAL ;
    PORT
      LAYER M4 ;
        RECT  0 42.528 0.084 42.552 ;
    END
  END rx_payload[399]
  PIN rx_payload[39]
    DIRECTION INPUT ;
    USE SIGNAL ;
    PORT
      LAYER M4 ;
        RECT  0 7.44 0.084 7.464 ;
    END
  END rx_payload[39]
  PIN rx_payload[3]
    DIRECTION INPUT ;
    USE SIGNAL ;
    PORT
      LAYER M4 ;
        RECT  0 3.936 0.084 3.96 ;
    END
  END rx_payload[3]
  PIN rx_payload[400]
    DIRECTION INPUT ;
    USE SIGNAL ;
    PORT
      LAYER M4 ;
        RECT  0 42.624 0.084 42.648 ;
    END
  END rx_payload[400]
  PIN rx_payload[401]
    DIRECTION INPUT ;
    USE SIGNAL ;
    PORT
      LAYER M4 ;
        RECT  0 42.72 0.084 42.744 ;
    END
  END rx_payload[401]
  PIN rx_payload[402]
    DIRECTION INPUT ;
    USE SIGNAL ;
    PORT
      LAYER M4 ;
        RECT  0 42.816 0.084 42.84 ;
    END
  END rx_payload[402]
  PIN rx_payload[403]
    DIRECTION INPUT ;
    USE SIGNAL ;
    PORT
      LAYER M4 ;
        RECT  0 42.912 0.084 42.936 ;
    END
  END rx_payload[403]
  PIN rx_payload[404]
    DIRECTION INPUT ;
    USE SIGNAL ;
    PORT
      LAYER M4 ;
        RECT  0 43.008 0.084 43.032 ;
    END
  END rx_payload[404]
  PIN rx_payload[405]
    DIRECTION INPUT ;
    USE SIGNAL ;
    PORT
      LAYER M4 ;
        RECT  0 43.104 0.084 43.128 ;
    END
  END rx_payload[405]
  PIN rx_payload[406]
    DIRECTION INPUT ;
    USE SIGNAL ;
    PORT
      LAYER M4 ;
        RECT  0 43.2 0.084 43.224 ;
    END
  END rx_payload[406]
  PIN rx_payload[407]
    DIRECTION INPUT ;
    USE SIGNAL ;
    PORT
      LAYER M4 ;
        RECT  0 43.296 0.084 43.32 ;
    END
  END rx_payload[407]
  PIN rx_payload[408]
    DIRECTION INPUT ;
    USE SIGNAL ;
    PORT
      LAYER M4 ;
        RECT  0 43.392 0.084 43.416 ;
    END
  END rx_payload[408]
  PIN rx_payload[409]
    DIRECTION INPUT ;
    USE SIGNAL ;
    PORT
      LAYER M4 ;
        RECT  0 43.488 0.084 43.512 ;
    END
  END rx_payload[409]
  PIN rx_payload[40]
    DIRECTION INPUT ;
    USE SIGNAL ;
    PORT
      LAYER M4 ;
        RECT  0 7.536 0.084 7.56 ;
    END
  END rx_payload[40]
  PIN rx_payload[410]
    DIRECTION INPUT ;
    USE SIGNAL ;
    PORT
      LAYER M4 ;
        RECT  0 43.584 0.084 43.608 ;
    END
  END rx_payload[410]
  PIN rx_payload[411]
    DIRECTION INPUT ;
    USE SIGNAL ;
    PORT
      LAYER M4 ;
        RECT  0 43.68 0.084 43.704 ;
    END
  END rx_payload[411]
  PIN rx_payload[412]
    DIRECTION INPUT ;
    USE SIGNAL ;
    PORT
      LAYER M4 ;
        RECT  0 43.776 0.084 43.8 ;
    END
  END rx_payload[412]
  PIN rx_payload[413]
    DIRECTION INPUT ;
    USE SIGNAL ;
    PORT
      LAYER M4 ;
        RECT  0 43.872 0.084 43.896 ;
    END
  END rx_payload[413]
  PIN rx_payload[414]
    DIRECTION INPUT ;
    USE SIGNAL ;
    PORT
      LAYER M4 ;
        RECT  0 43.968 0.084 43.992 ;
    END
  END rx_payload[414]
  PIN rx_payload[415]
    DIRECTION INPUT ;
    USE SIGNAL ;
    PORT
      LAYER M4 ;
        RECT  0 44.064 0.084 44.088 ;
    END
  END rx_payload[415]
  PIN rx_payload[416]
    DIRECTION INPUT ;
    USE SIGNAL ;
    PORT
      LAYER M4 ;
        RECT  0 44.16 0.084 44.184 ;
    END
  END rx_payload[416]
  PIN rx_payload[417]
    DIRECTION INPUT ;
    USE SIGNAL ;
    PORT
      LAYER M4 ;
        RECT  0 44.256 0.084 44.28 ;
    END
  END rx_payload[417]
  PIN rx_payload[418]
    DIRECTION INPUT ;
    USE SIGNAL ;
    PORT
      LAYER M4 ;
        RECT  0 44.352 0.084 44.376 ;
    END
  END rx_payload[418]
  PIN rx_payload[419]
    DIRECTION INPUT ;
    USE SIGNAL ;
    PORT
      LAYER M4 ;
        RECT  0 44.448 0.084 44.472 ;
    END
  END rx_payload[419]
  PIN rx_payload[41]
    DIRECTION INPUT ;
    USE SIGNAL ;
    PORT
      LAYER M4 ;
        RECT  0 7.632 0.084 7.656 ;
    END
  END rx_payload[41]
  PIN rx_payload[420]
    DIRECTION INPUT ;
    USE SIGNAL ;
    PORT
      LAYER M4 ;
        RECT  0 44.544 0.084 44.568 ;
    END
  END rx_payload[420]
  PIN rx_payload[421]
    DIRECTION INPUT ;
    USE SIGNAL ;
    PORT
      LAYER M4 ;
        RECT  0 44.64 0.084 44.664 ;
    END
  END rx_payload[421]
  PIN rx_payload[422]
    DIRECTION INPUT ;
    USE SIGNAL ;
    PORT
      LAYER M4 ;
        RECT  0 44.736 0.084 44.76 ;
    END
  END rx_payload[422]
  PIN rx_payload[423]
    DIRECTION INPUT ;
    USE SIGNAL ;
    PORT
      LAYER M4 ;
        RECT  0 44.88 0.084 44.904 ;
    END
  END rx_payload[423]
  PIN rx_payload[424]
    DIRECTION INPUT ;
    USE SIGNAL ;
    PORT
      LAYER M4 ;
        RECT  0 44.976 0.084 45 ;
    END
  END rx_payload[424]
  PIN rx_payload[425]
    DIRECTION INPUT ;
    USE SIGNAL ;
    PORT
      LAYER M4 ;
        RECT  0 45.072 0.084 45.096 ;
    END
  END rx_payload[425]
  PIN rx_payload[426]
    DIRECTION INPUT ;
    USE SIGNAL ;
    PORT
      LAYER M4 ;
        RECT  0 45.168 0.084 45.192 ;
    END
  END rx_payload[426]
  PIN rx_payload[427]
    DIRECTION INPUT ;
    USE SIGNAL ;
    PORT
      LAYER M4 ;
        RECT  0 45.264 0.084 45.288 ;
    END
  END rx_payload[427]
  PIN rx_payload[428]
    DIRECTION INPUT ;
    USE SIGNAL ;
    PORT
      LAYER M4 ;
        RECT  0 45.36 0.084 45.384 ;
    END
  END rx_payload[428]
  PIN rx_payload[429]
    DIRECTION INPUT ;
    USE SIGNAL ;
    PORT
      LAYER M4 ;
        RECT  0 45.456 0.084 45.48 ;
    END
  END rx_payload[429]
  PIN rx_payload[42]
    DIRECTION INPUT ;
    USE SIGNAL ;
    PORT
      LAYER M4 ;
        RECT  0 7.728 0.084 7.752 ;
    END
  END rx_payload[42]
  PIN rx_payload[430]
    DIRECTION INPUT ;
    USE SIGNAL ;
    PORT
      LAYER M4 ;
        RECT  0 45.552 0.084 45.576 ;
    END
  END rx_payload[430]
  PIN rx_payload[431]
    DIRECTION INPUT ;
    USE SIGNAL ;
    PORT
      LAYER M4 ;
        RECT  0 45.648 0.084 45.672 ;
    END
  END rx_payload[431]
  PIN rx_payload[432]
    DIRECTION INPUT ;
    USE SIGNAL ;
    PORT
      LAYER M4 ;
        RECT  0 45.744 0.084 45.768 ;
    END
  END rx_payload[432]
  PIN rx_payload[433]
    DIRECTION INPUT ;
    USE SIGNAL ;
    PORT
      LAYER M4 ;
        RECT  0 45.84 0.084 45.864 ;
    END
  END rx_payload[433]
  PIN rx_payload[434]
    DIRECTION INPUT ;
    USE SIGNAL ;
    PORT
      LAYER M4 ;
        RECT  0 45.936 0.084 45.96 ;
    END
  END rx_payload[434]
  PIN rx_payload[435]
    DIRECTION INPUT ;
    USE SIGNAL ;
    PORT
      LAYER M4 ;
        RECT  0 46.032 0.084 46.056 ;
    END
  END rx_payload[435]
  PIN rx_payload[436]
    DIRECTION INPUT ;
    USE SIGNAL ;
    PORT
      LAYER M4 ;
        RECT  0 46.128 0.084 46.152 ;
    END
  END rx_payload[436]
  PIN rx_payload[437]
    DIRECTION INPUT ;
    USE SIGNAL ;
    PORT
      LAYER M4 ;
        RECT  0 46.224 0.084 46.248 ;
    END
  END rx_payload[437]
  PIN rx_payload[438]
    DIRECTION INPUT ;
    USE SIGNAL ;
    PORT
      LAYER M4 ;
        RECT  0 46.32 0.084 46.344 ;
    END
  END rx_payload[438]
  PIN rx_payload[439]
    DIRECTION INPUT ;
    USE SIGNAL ;
    PORT
      LAYER M4 ;
        RECT  0 46.416 0.084 46.44 ;
    END
  END rx_payload[439]
  PIN rx_payload[43]
    DIRECTION INPUT ;
    USE SIGNAL ;
    PORT
      LAYER M4 ;
        RECT  0 7.824 0.084 7.848 ;
    END
  END rx_payload[43]
  PIN rx_payload[440]
    DIRECTION INPUT ;
    USE SIGNAL ;
    PORT
      LAYER M4 ;
        RECT  0 46.512 0.084 46.536 ;
    END
  END rx_payload[440]
  PIN rx_payload[441]
    DIRECTION INPUT ;
    USE SIGNAL ;
    PORT
      LAYER M4 ;
        RECT  0 46.608 0.084 46.632 ;
    END
  END rx_payload[441]
  PIN rx_payload[442]
    DIRECTION INPUT ;
    USE SIGNAL ;
    PORT
      LAYER M4 ;
        RECT  0 46.704 0.084 46.728 ;
    END
  END rx_payload[442]
  PIN rx_payload[443]
    DIRECTION INPUT ;
    USE SIGNAL ;
    PORT
      LAYER M4 ;
        RECT  0 46.8 0.084 46.824 ;
    END
  END rx_payload[443]
  PIN rx_payload[444]
    DIRECTION INPUT ;
    USE SIGNAL ;
    PORT
      LAYER M4 ;
        RECT  0 46.896 0.084 46.92 ;
    END
  END rx_payload[444]
  PIN rx_payload[445]
    DIRECTION INPUT ;
    USE SIGNAL ;
    PORT
      LAYER M4 ;
        RECT  0 46.992 0.084 47.016 ;
    END
  END rx_payload[445]
  PIN rx_payload[446]
    DIRECTION INPUT ;
    USE SIGNAL ;
    PORT
      LAYER M4 ;
        RECT  0 47.088 0.084 47.112 ;
    END
  END rx_payload[446]
  PIN rx_payload[447]
    DIRECTION INPUT ;
    USE SIGNAL ;
    PORT
      LAYER M4 ;
        RECT  0 47.184 0.084 47.208 ;
    END
  END rx_payload[447]
  PIN rx_payload[448]
    DIRECTION INPUT ;
    USE SIGNAL ;
    PORT
      LAYER M4 ;
        RECT  0 47.28 0.084 47.304 ;
    END
  END rx_payload[448]
  PIN rx_payload[449]
    DIRECTION INPUT ;
    USE SIGNAL ;
    PORT
      LAYER M4 ;
        RECT  0 47.376 0.084 47.4 ;
    END
  END rx_payload[449]
  PIN rx_payload[44]
    DIRECTION INPUT ;
    USE SIGNAL ;
    PORT
      LAYER M4 ;
        RECT  0 7.92 0.084 7.944 ;
    END
  END rx_payload[44]
  PIN rx_payload[450]
    DIRECTION INPUT ;
    USE SIGNAL ;
    PORT
      LAYER M4 ;
        RECT  0 47.472 0.084 47.496 ;
    END
  END rx_payload[450]
  PIN rx_payload[451]
    DIRECTION INPUT ;
    USE SIGNAL ;
    PORT
      LAYER M4 ;
        RECT  0 47.568 0.084 47.592 ;
    END
  END rx_payload[451]
  PIN rx_payload[452]
    DIRECTION INPUT ;
    USE SIGNAL ;
    PORT
      LAYER M4 ;
        RECT  0 47.664 0.084 47.688 ;
    END
  END rx_payload[452]
  PIN rx_payload[453]
    DIRECTION INPUT ;
    USE SIGNAL ;
    PORT
      LAYER M4 ;
        RECT  0 47.76 0.084 47.784 ;
    END
  END rx_payload[453]
  PIN rx_payload[454]
    DIRECTION INPUT ;
    USE SIGNAL ;
    PORT
      LAYER M4 ;
        RECT  0 47.856 0.084 47.88 ;
    END
  END rx_payload[454]
  PIN rx_payload[455]
    DIRECTION INPUT ;
    USE SIGNAL ;
    PORT
      LAYER M4 ;
        RECT  0 47.952 0.084 47.976 ;
    END
  END rx_payload[455]
  PIN rx_payload[456]
    DIRECTION INPUT ;
    USE SIGNAL ;
    PORT
      LAYER M4 ;
        RECT  0 48.096 0.084 48.12 ;
    END
  END rx_payload[456]
  PIN rx_payload[457]
    DIRECTION INPUT ;
    USE SIGNAL ;
    PORT
      LAYER M4 ;
        RECT  0 48.192 0.084 48.216 ;
    END
  END rx_payload[457]
  PIN rx_payload[458]
    DIRECTION INPUT ;
    USE SIGNAL ;
    PORT
      LAYER M4 ;
        RECT  0 48.288 0.084 48.312 ;
    END
  END rx_payload[458]
  PIN rx_payload[459]
    DIRECTION INPUT ;
    USE SIGNAL ;
    PORT
      LAYER M4 ;
        RECT  0 48.384 0.084 48.408 ;
    END
  END rx_payload[459]
  PIN rx_payload[45]
    DIRECTION INPUT ;
    USE SIGNAL ;
    PORT
      LAYER M4 ;
        RECT  0 8.016 0.084 8.04 ;
    END
  END rx_payload[45]
  PIN rx_payload[460]
    DIRECTION INPUT ;
    USE SIGNAL ;
    PORT
      LAYER M4 ;
        RECT  0 48.48 0.084 48.504 ;
    END
  END rx_payload[460]
  PIN rx_payload[461]
    DIRECTION INPUT ;
    USE SIGNAL ;
    PORT
      LAYER M4 ;
        RECT  0 48.576 0.084 48.6 ;
    END
  END rx_payload[461]
  PIN rx_payload[462]
    DIRECTION INPUT ;
    USE SIGNAL ;
    PORT
      LAYER M4 ;
        RECT  0 48.672 0.084 48.696 ;
    END
  END rx_payload[462]
  PIN rx_payload[463]
    DIRECTION INPUT ;
    USE SIGNAL ;
    PORT
      LAYER M4 ;
        RECT  0 48.768 0.084 48.792 ;
    END
  END rx_payload[463]
  PIN rx_payload[464]
    DIRECTION INPUT ;
    USE SIGNAL ;
    PORT
      LAYER M4 ;
        RECT  0 48.864 0.084 48.888 ;
    END
  END rx_payload[464]
  PIN rx_payload[465]
    DIRECTION INPUT ;
    USE SIGNAL ;
    PORT
      LAYER M4 ;
        RECT  0 48.96 0.084 48.984 ;
    END
  END rx_payload[465]
  PIN rx_payload[466]
    DIRECTION INPUT ;
    USE SIGNAL ;
    PORT
      LAYER M4 ;
        RECT  0 49.056 0.084 49.08 ;
    END
  END rx_payload[466]
  PIN rx_payload[467]
    DIRECTION INPUT ;
    USE SIGNAL ;
    PORT
      LAYER M4 ;
        RECT  0 49.152 0.084 49.176 ;
    END
  END rx_payload[467]
  PIN rx_payload[468]
    DIRECTION INPUT ;
    USE SIGNAL ;
    PORT
      LAYER M4 ;
        RECT  0 49.248 0.084 49.272 ;
    END
  END rx_payload[468]
  PIN rx_payload[469]
    DIRECTION INPUT ;
    USE SIGNAL ;
    PORT
      LAYER M4 ;
        RECT  0 49.344 0.084 49.368 ;
    END
  END rx_payload[469]
  PIN rx_payload[46]
    DIRECTION INPUT ;
    USE SIGNAL ;
    PORT
      LAYER M4 ;
        RECT  0 8.112 0.084 8.136 ;
    END
  END rx_payload[46]
  PIN rx_payload[470]
    DIRECTION INPUT ;
    USE SIGNAL ;
    PORT
      LAYER M4 ;
        RECT  0 49.44 0.084 49.464 ;
    END
  END rx_payload[470]
  PIN rx_payload[471]
    DIRECTION INPUT ;
    USE SIGNAL ;
    PORT
      LAYER M4 ;
        RECT  0 49.536 0.084 49.56 ;
    END
  END rx_payload[471]
  PIN rx_payload[472]
    DIRECTION INPUT ;
    USE SIGNAL ;
    PORT
      LAYER M4 ;
        RECT  0 49.632 0.084 49.656 ;
    END
  END rx_payload[472]
  PIN rx_payload[473]
    DIRECTION INPUT ;
    USE SIGNAL ;
    PORT
      LAYER M4 ;
        RECT  0 49.728 0.084 49.752 ;
    END
  END rx_payload[473]
  PIN rx_payload[474]
    DIRECTION INPUT ;
    USE SIGNAL ;
    PORT
      LAYER M4 ;
        RECT  0 49.824 0.084 49.848 ;
    END
  END rx_payload[474]
  PIN rx_payload[475]
    DIRECTION INPUT ;
    USE SIGNAL ;
    PORT
      LAYER M4 ;
        RECT  0 49.92 0.084 49.944 ;
    END
  END rx_payload[475]
  PIN rx_payload[476]
    DIRECTION INPUT ;
    USE SIGNAL ;
    PORT
      LAYER M4 ;
        RECT  0 50.016 0.084 50.04 ;
    END
  END rx_payload[476]
  PIN rx_payload[477]
    DIRECTION INPUT ;
    USE SIGNAL ;
    PORT
      LAYER M4 ;
        RECT  0 50.112 0.084 50.136 ;
    END
  END rx_payload[477]
  PIN rx_payload[478]
    DIRECTION INPUT ;
    USE SIGNAL ;
    PORT
      LAYER M4 ;
        RECT  0 50.208 0.084 50.232 ;
    END
  END rx_payload[478]
  PIN rx_payload[479]
    DIRECTION INPUT ;
    USE SIGNAL ;
    PORT
      LAYER M4 ;
        RECT  0 50.304 0.084 50.328 ;
    END
  END rx_payload[479]
  PIN rx_payload[47]
    DIRECTION INPUT ;
    USE SIGNAL ;
    PORT
      LAYER M4 ;
        RECT  0 8.208 0.084 8.232 ;
    END
  END rx_payload[47]
  PIN rx_payload[480]
    DIRECTION INPUT ;
    USE SIGNAL ;
    PORT
      LAYER M4 ;
        RECT  0 50.4 0.084 50.424 ;
    END
  END rx_payload[480]
  PIN rx_payload[481]
    DIRECTION INPUT ;
    USE SIGNAL ;
    PORT
      LAYER M4 ;
        RECT  0 50.496 0.084 50.52 ;
    END
  END rx_payload[481]
  PIN rx_payload[482]
    DIRECTION INPUT ;
    USE SIGNAL ;
    PORT
      LAYER M4 ;
        RECT  0 50.592 0.084 50.616 ;
    END
  END rx_payload[482]
  PIN rx_payload[483]
    DIRECTION INPUT ;
    USE SIGNAL ;
    PORT
      LAYER M4 ;
        RECT  0 50.688 0.084 50.712 ;
    END
  END rx_payload[483]
  PIN rx_payload[484]
    DIRECTION INPUT ;
    USE SIGNAL ;
    PORT
      LAYER M4 ;
        RECT  0 50.784 0.084 50.808 ;
    END
  END rx_payload[484]
  PIN rx_payload[485]
    DIRECTION INPUT ;
    USE SIGNAL ;
    PORT
      LAYER M4 ;
        RECT  0 50.88 0.084 50.904 ;
    END
  END rx_payload[485]
  PIN rx_payload[486]
    DIRECTION INPUT ;
    USE SIGNAL ;
    PORT
      LAYER M4 ;
        RECT  0 50.976 0.084 51 ;
    END
  END rx_payload[486]
  PIN rx_payload[487]
    DIRECTION INPUT ;
    USE SIGNAL ;
    PORT
      LAYER M4 ;
        RECT  0 51.072 0.084 51.096 ;
    END
  END rx_payload[487]
  PIN rx_payload[488]
    DIRECTION INPUT ;
    USE SIGNAL ;
    PORT
      LAYER M4 ;
        RECT  0 51.168 0.084 51.192 ;
    END
  END rx_payload[488]
  PIN rx_payload[489]
    DIRECTION INPUT ;
    USE SIGNAL ;
    PORT
      LAYER M4 ;
        RECT  0 51.264 0.084 51.288 ;
    END
  END rx_payload[489]
  PIN rx_payload[48]
    DIRECTION INPUT ;
    USE SIGNAL ;
    PORT
      LAYER M4 ;
        RECT  0 8.304 0.084 8.328 ;
    END
  END rx_payload[48]
  PIN rx_payload[490]
    DIRECTION INPUT ;
    USE SIGNAL ;
    PORT
      LAYER M4 ;
        RECT  0 51.408 0.084 51.432 ;
    END
  END rx_payload[490]
  PIN rx_payload[491]
    DIRECTION INPUT ;
    USE SIGNAL ;
    PORT
      LAYER M4 ;
        RECT  0 51.504 0.084 51.528 ;
    END
  END rx_payload[491]
  PIN rx_payload[492]
    DIRECTION INPUT ;
    USE SIGNAL ;
    PORT
      LAYER M4 ;
        RECT  0 51.6 0.084 51.624 ;
    END
  END rx_payload[492]
  PIN rx_payload[493]
    DIRECTION INPUT ;
    USE SIGNAL ;
    PORT
      LAYER M4 ;
        RECT  0 51.696 0.084 51.72 ;
    END
  END rx_payload[493]
  PIN rx_payload[494]
    DIRECTION INPUT ;
    USE SIGNAL ;
    PORT
      LAYER M4 ;
        RECT  0 51.792 0.084 51.816 ;
    END
  END rx_payload[494]
  PIN rx_payload[495]
    DIRECTION INPUT ;
    USE SIGNAL ;
    PORT
      LAYER M4 ;
        RECT  0 51.888 0.084 51.912 ;
    END
  END rx_payload[495]
  PIN rx_payload[496]
    DIRECTION INPUT ;
    USE SIGNAL ;
    PORT
      LAYER M4 ;
        RECT  0 51.984 0.084 52.008 ;
    END
  END rx_payload[496]
  PIN rx_payload[497]
    DIRECTION INPUT ;
    USE SIGNAL ;
    PORT
      LAYER M4 ;
        RECT  0 52.08 0.084 52.104 ;
    END
  END rx_payload[497]
  PIN rx_payload[498]
    DIRECTION INPUT ;
    USE SIGNAL ;
    PORT
      LAYER M4 ;
        RECT  0 52.176 0.084 52.2 ;
    END
  END rx_payload[498]
  PIN rx_payload[499]
    DIRECTION INPUT ;
    USE SIGNAL ;
    PORT
      LAYER M4 ;
        RECT  0 52.272 0.084 52.296 ;
    END
  END rx_payload[499]
  PIN rx_payload[49]
    DIRECTION INPUT ;
    USE SIGNAL ;
    PORT
      LAYER M4 ;
        RECT  0 8.4 0.084 8.424 ;
    END
  END rx_payload[49]
  PIN rx_payload[4]
    DIRECTION INPUT ;
    USE SIGNAL ;
    PORT
      LAYER M4 ;
        RECT  0 4.032 0.084 4.056 ;
    END
  END rx_payload[4]
  PIN rx_payload[500]
    DIRECTION INPUT ;
    USE SIGNAL ;
    PORT
      LAYER M4 ;
        RECT  0 52.368 0.084 52.392 ;
    END
  END rx_payload[500]
  PIN rx_payload[501]
    DIRECTION INPUT ;
    USE SIGNAL ;
    PORT
      LAYER M4 ;
        RECT  0 52.464 0.084 52.488 ;
    END
  END rx_payload[501]
  PIN rx_payload[502]
    DIRECTION INPUT ;
    USE SIGNAL ;
    PORT
      LAYER M4 ;
        RECT  0 52.56 0.084 52.584 ;
    END
  END rx_payload[502]
  PIN rx_payload[503]
    DIRECTION INPUT ;
    USE SIGNAL ;
    PORT
      LAYER M4 ;
        RECT  0 52.656 0.084 52.68 ;
    END
  END rx_payload[503]
  PIN rx_payload[504]
    DIRECTION INPUT ;
    USE SIGNAL ;
    PORT
      LAYER M4 ;
        RECT  0 52.752 0.084 52.776 ;
    END
  END rx_payload[504]
  PIN rx_payload[505]
    DIRECTION INPUT ;
    USE SIGNAL ;
    PORT
      LAYER M4 ;
        RECT  0 52.848 0.084 52.872 ;
    END
  END rx_payload[505]
  PIN rx_payload[506]
    DIRECTION INPUT ;
    USE SIGNAL ;
    PORT
      LAYER M4 ;
        RECT  0 52.944 0.084 52.968 ;
    END
  END rx_payload[506]
  PIN rx_payload[507]
    DIRECTION INPUT ;
    USE SIGNAL ;
    PORT
      LAYER M4 ;
        RECT  0 53.04 0.084 53.064 ;
    END
  END rx_payload[507]
  PIN rx_payload[508]
    DIRECTION INPUT ;
    USE SIGNAL ;
    PORT
      LAYER M4 ;
        RECT  0 53.136 0.084 53.16 ;
    END
  END rx_payload[508]
  PIN rx_payload[509]
    DIRECTION INPUT ;
    USE SIGNAL ;
    PORT
      LAYER M4 ;
        RECT  0 53.232 0.084 53.256 ;
    END
  END rx_payload[509]
  PIN rx_payload[50]
    DIRECTION INPUT ;
    USE SIGNAL ;
    PORT
      LAYER M4 ;
        RECT  0 8.496 0.084 8.52 ;
    END
  END rx_payload[50]
  PIN rx_payload[510]
    DIRECTION INPUT ;
    USE SIGNAL ;
    PORT
      LAYER M4 ;
        RECT  0 53.328 0.084 53.352 ;
    END
  END rx_payload[510]
  PIN rx_payload[511]
    DIRECTION INPUT ;
    USE SIGNAL ;
    PORT
      LAYER M4 ;
        RECT  0 53.424 0.084 53.448 ;
    END
  END rx_payload[511]
  PIN rx_payload[512]
    DIRECTION INPUT ;
    USE SIGNAL ;
    PORT
      LAYER M4 ;
        RECT  0 53.52 0.084 53.544 ;
    END
  END rx_payload[512]
  PIN rx_payload[513]
    DIRECTION INPUT ;
    USE SIGNAL ;
    PORT
      LAYER M4 ;
        RECT  0 53.616 0.084 53.64 ;
    END
  END rx_payload[513]
  PIN rx_payload[514]
    DIRECTION INPUT ;
    USE SIGNAL ;
    PORT
      LAYER M4 ;
        RECT  0 53.712 0.084 53.736 ;
    END
  END rx_payload[514]
  PIN rx_payload[515]
    DIRECTION INPUT ;
    USE SIGNAL ;
    PORT
      LAYER M4 ;
        RECT  0 53.808 0.084 53.832 ;
    END
  END rx_payload[515]
  PIN rx_payload[516]
    DIRECTION INPUT ;
    USE SIGNAL ;
    PORT
      LAYER M4 ;
        RECT  0 53.904 0.084 53.928 ;
    END
  END rx_payload[516]
  PIN rx_payload[517]
    DIRECTION INPUT ;
    USE SIGNAL ;
    PORT
      LAYER M4 ;
        RECT  0 54 0.084 54.024 ;
    END
  END rx_payload[517]
  PIN rx_payload[518]
    DIRECTION INPUT ;
    USE SIGNAL ;
    PORT
      LAYER M4 ;
        RECT  0 54.096 0.084 54.12 ;
    END
  END rx_payload[518]
  PIN rx_payload[519]
    DIRECTION INPUT ;
    USE SIGNAL ;
    PORT
      LAYER M4 ;
        RECT  0 54.192 0.084 54.216 ;
    END
  END rx_payload[519]
  PIN rx_payload[51]
    DIRECTION INPUT ;
    USE SIGNAL ;
    PORT
      LAYER M4 ;
        RECT  0 8.592 0.084 8.616 ;
    END
  END rx_payload[51]
  PIN rx_payload[520]
    DIRECTION INPUT ;
    USE SIGNAL ;
    PORT
      LAYER M4 ;
        RECT  0 54.288 0.084 54.312 ;
    END
  END rx_payload[520]
  PIN rx_payload[521]
    DIRECTION INPUT ;
    USE SIGNAL ;
    PORT
      LAYER M4 ;
        RECT  0 54.384 0.084 54.408 ;
    END
  END rx_payload[521]
  PIN rx_payload[522]
    DIRECTION INPUT ;
    USE SIGNAL ;
    PORT
      LAYER M4 ;
        RECT  0 54.48 0.084 54.504 ;
    END
  END rx_payload[522]
  PIN rx_payload[523]
    DIRECTION INPUT ;
    USE SIGNAL ;
    PORT
      LAYER M4 ;
        RECT  0 54.624 0.084 54.648 ;
    END
  END rx_payload[523]
  PIN rx_payload[524]
    DIRECTION INPUT ;
    USE SIGNAL ;
    PORT
      LAYER M4 ;
        RECT  0 54.72 0.084 54.744 ;
    END
  END rx_payload[524]
  PIN rx_payload[525]
    DIRECTION INPUT ;
    USE SIGNAL ;
    PORT
      LAYER M4 ;
        RECT  0 54.816 0.084 54.84 ;
    END
  END rx_payload[525]
  PIN rx_payload[526]
    DIRECTION INPUT ;
    USE SIGNAL ;
    PORT
      LAYER M4 ;
        RECT  0 54.912 0.084 54.936 ;
    END
  END rx_payload[526]
  PIN rx_payload[527]
    DIRECTION INPUT ;
    USE SIGNAL ;
    PORT
      LAYER M4 ;
        RECT  0 55.008 0.084 55.032 ;
    END
  END rx_payload[527]
  PIN rx_payload[528]
    DIRECTION INPUT ;
    USE SIGNAL ;
    PORT
      LAYER M4 ;
        RECT  0 55.104 0.084 55.128 ;
    END
  END rx_payload[528]
  PIN rx_payload[529]
    DIRECTION INPUT ;
    USE SIGNAL ;
    PORT
      LAYER M4 ;
        RECT  0 55.2 0.084 55.224 ;
    END
  END rx_payload[529]
  PIN rx_payload[52]
    DIRECTION INPUT ;
    USE SIGNAL ;
    PORT
      LAYER M4 ;
        RECT  0 8.688 0.084 8.712 ;
    END
  END rx_payload[52]
  PIN rx_payload[530]
    DIRECTION INPUT ;
    USE SIGNAL ;
    PORT
      LAYER M4 ;
        RECT  0 55.296 0.084 55.32 ;
    END
  END rx_payload[530]
  PIN rx_payload[531]
    DIRECTION INPUT ;
    USE SIGNAL ;
    PORT
      LAYER M4 ;
        RECT  0 55.392 0.084 55.416 ;
    END
  END rx_payload[531]
  PIN rx_payload[532]
    DIRECTION INPUT ;
    USE SIGNAL ;
    PORT
      LAYER M4 ;
        RECT  0 55.488 0.084 55.512 ;
    END
  END rx_payload[532]
  PIN rx_payload[533]
    DIRECTION INPUT ;
    USE SIGNAL ;
    PORT
      LAYER M4 ;
        RECT  0 55.584 0.084 55.608 ;
    END
  END rx_payload[533]
  PIN rx_payload[534]
    DIRECTION INPUT ;
    USE SIGNAL ;
    PORT
      LAYER M4 ;
        RECT  0 55.68 0.084 55.704 ;
    END
  END rx_payload[534]
  PIN rx_payload[535]
    DIRECTION INPUT ;
    USE SIGNAL ;
    PORT
      LAYER M4 ;
        RECT  0 55.776 0.084 55.8 ;
    END
  END rx_payload[535]
  PIN rx_payload[536]
    DIRECTION INPUT ;
    USE SIGNAL ;
    PORT
      LAYER M4 ;
        RECT  0 55.872 0.084 55.896 ;
    END
  END rx_payload[536]
  PIN rx_payload[537]
    DIRECTION INPUT ;
    USE SIGNAL ;
    PORT
      LAYER M4 ;
        RECT  0 55.968 0.084 55.992 ;
    END
  END rx_payload[537]
  PIN rx_payload[538]
    DIRECTION INPUT ;
    USE SIGNAL ;
    PORT
      LAYER M4 ;
        RECT  0 56.064 0.084 56.088 ;
    END
  END rx_payload[538]
  PIN rx_payload[539]
    DIRECTION INPUT ;
    USE SIGNAL ;
    PORT
      LAYER M4 ;
        RECT  0 56.16 0.084 56.184 ;
    END
  END rx_payload[539]
  PIN rx_payload[53]
    DIRECTION INPUT ;
    USE SIGNAL ;
    PORT
      LAYER M4 ;
        RECT  0 8.784 0.084 8.808 ;
    END
  END rx_payload[53]
  PIN rx_payload[540]
    DIRECTION INPUT ;
    USE SIGNAL ;
    PORT
      LAYER M4 ;
        RECT  0 56.256 0.084 56.28 ;
    END
  END rx_payload[540]
  PIN rx_payload[541]
    DIRECTION INPUT ;
    USE SIGNAL ;
    PORT
      LAYER M4 ;
        RECT  0 56.352 0.084 56.376 ;
    END
  END rx_payload[541]
  PIN rx_payload[542]
    DIRECTION INPUT ;
    USE SIGNAL ;
    PORT
      LAYER M4 ;
        RECT  0 56.448 0.084 56.472 ;
    END
  END rx_payload[542]
  PIN rx_payload[543]
    DIRECTION INPUT ;
    USE SIGNAL ;
    PORT
      LAYER M4 ;
        RECT  0 56.544 0.084 56.568 ;
    END
  END rx_payload[543]
  PIN rx_payload[544]
    DIRECTION INPUT ;
    USE SIGNAL ;
    PORT
      LAYER M4 ;
        RECT  0 56.64 0.084 56.664 ;
    END
  END rx_payload[544]
  PIN rx_payload[545]
    DIRECTION INPUT ;
    USE SIGNAL ;
    PORT
      LAYER M4 ;
        RECT  0 56.736 0.084 56.76 ;
    END
  END rx_payload[545]
  PIN rx_payload[546]
    DIRECTION INPUT ;
    USE SIGNAL ;
    PORT
      LAYER M4 ;
        RECT  0 56.832 0.084 56.856 ;
    END
  END rx_payload[546]
  PIN rx_payload[547]
    DIRECTION INPUT ;
    USE SIGNAL ;
    PORT
      LAYER M4 ;
        RECT  0 56.928 0.084 56.952 ;
    END
  END rx_payload[547]
  PIN rx_payload[54]
    DIRECTION INPUT ;
    USE SIGNAL ;
    PORT
      LAYER M4 ;
        RECT  0 8.88 0.084 8.904 ;
    END
  END rx_payload[54]
  PIN rx_payload[55]
    DIRECTION INPUT ;
    USE SIGNAL ;
    PORT
      LAYER M4 ;
        RECT  0 8.976 0.084 9 ;
    END
  END rx_payload[55]
  PIN rx_payload[56]
    DIRECTION INPUT ;
    USE SIGNAL ;
    PORT
      LAYER M4 ;
        RECT  0 9.072 0.084 9.096 ;
    END
  END rx_payload[56]
  PIN rx_payload[57]
    DIRECTION INPUT ;
    USE SIGNAL ;
    PORT
      LAYER M4 ;
        RECT  0 9.168 0.084 9.192 ;
    END
  END rx_payload[57]
  PIN rx_payload[58]
    DIRECTION INPUT ;
    USE SIGNAL ;
    PORT
      LAYER M4 ;
        RECT  0 9.312 0.084 9.336 ;
    END
  END rx_payload[58]
  PIN rx_payload[59]
    DIRECTION INPUT ;
    USE SIGNAL ;
    PORT
      LAYER M4 ;
        RECT  0 9.408 0.084 9.432 ;
    END
  END rx_payload[59]
  PIN rx_payload[5]
    DIRECTION INPUT ;
    USE SIGNAL ;
    PORT
      LAYER M4 ;
        RECT  0 4.128 0.084 4.152 ;
    END
  END rx_payload[5]
  PIN rx_payload[60]
    DIRECTION INPUT ;
    USE SIGNAL ;
    PORT
      LAYER M4 ;
        RECT  0 9.504 0.084 9.528 ;
    END
  END rx_payload[60]
  PIN rx_payload[61]
    DIRECTION INPUT ;
    USE SIGNAL ;
    PORT
      LAYER M4 ;
        RECT  0 9.6 0.084 9.624 ;
    END
  END rx_payload[61]
  PIN rx_payload[62]
    DIRECTION INPUT ;
    USE SIGNAL ;
    PORT
      LAYER M4 ;
        RECT  0 9.696 0.084 9.72 ;
    END
  END rx_payload[62]
  PIN rx_payload[63]
    DIRECTION INPUT ;
    USE SIGNAL ;
    PORT
      LAYER M4 ;
        RECT  0 9.792 0.084 9.816 ;
    END
  END rx_payload[63]
  PIN rx_payload[64]
    DIRECTION INPUT ;
    USE SIGNAL ;
    PORT
      LAYER M4 ;
        RECT  0 9.888 0.084 9.912 ;
    END
  END rx_payload[64]
  PIN rx_payload[65]
    DIRECTION INPUT ;
    USE SIGNAL ;
    PORT
      LAYER M4 ;
        RECT  0 9.984 0.084 10.008 ;
    END
  END rx_payload[65]
  PIN rx_payload[66]
    DIRECTION INPUT ;
    USE SIGNAL ;
    PORT
      LAYER M4 ;
        RECT  0 10.08 0.084 10.104 ;
    END
  END rx_payload[66]
  PIN rx_payload[67]
    DIRECTION INPUT ;
    USE SIGNAL ;
    PORT
      LAYER M4 ;
        RECT  0 10.176 0.084 10.2 ;
    END
  END rx_payload[67]
  PIN rx_payload[68]
    DIRECTION INPUT ;
    USE SIGNAL ;
    PORT
      LAYER M4 ;
        RECT  0 10.272 0.084 10.296 ;
    END
  END rx_payload[68]
  PIN rx_payload[69]
    DIRECTION INPUT ;
    USE SIGNAL ;
    PORT
      LAYER M4 ;
        RECT  0 10.368 0.084 10.392 ;
    END
  END rx_payload[69]
  PIN rx_payload[6]
    DIRECTION INPUT ;
    USE SIGNAL ;
    PORT
      LAYER M4 ;
        RECT  0 4.224 0.084 4.248 ;
    END
  END rx_payload[6]
  PIN rx_payload[70]
    DIRECTION INPUT ;
    USE SIGNAL ;
    PORT
      LAYER M4 ;
        RECT  0 10.464 0.084 10.488 ;
    END
  END rx_payload[70]
  PIN rx_payload[71]
    DIRECTION INPUT ;
    USE SIGNAL ;
    PORT
      LAYER M4 ;
        RECT  0 10.56 0.084 10.584 ;
    END
  END rx_payload[71]
  PIN rx_payload[72]
    DIRECTION INPUT ;
    USE SIGNAL ;
    PORT
      LAYER M4 ;
        RECT  0 10.656 0.084 10.68 ;
    END
  END rx_payload[72]
  PIN rx_payload[73]
    DIRECTION INPUT ;
    USE SIGNAL ;
    PORT
      LAYER M4 ;
        RECT  0 10.752 0.084 10.776 ;
    END
  END rx_payload[73]
  PIN rx_payload[74]
    DIRECTION INPUT ;
    USE SIGNAL ;
    PORT
      LAYER M4 ;
        RECT  0 10.848 0.084 10.872 ;
    END
  END rx_payload[74]
  PIN rx_payload[75]
    DIRECTION INPUT ;
    USE SIGNAL ;
    PORT
      LAYER M4 ;
        RECT  0 10.944 0.084 10.968 ;
    END
  END rx_payload[75]
  PIN rx_payload[76]
    DIRECTION INPUT ;
    USE SIGNAL ;
    PORT
      LAYER M4 ;
        RECT  0 11.04 0.084 11.064 ;
    END
  END rx_payload[76]
  PIN rx_payload[77]
    DIRECTION INPUT ;
    USE SIGNAL ;
    PORT
      LAYER M4 ;
        RECT  0 11.136 0.084 11.16 ;
    END
  END rx_payload[77]
  PIN rx_payload[78]
    DIRECTION INPUT ;
    USE SIGNAL ;
    PORT
      LAYER M4 ;
        RECT  0 11.232 0.084 11.256 ;
    END
  END rx_payload[78]
  PIN rx_payload[79]
    DIRECTION INPUT ;
    USE SIGNAL ;
    PORT
      LAYER M4 ;
        RECT  0 11.328 0.084 11.352 ;
    END
  END rx_payload[79]
  PIN rx_payload[7]
    DIRECTION INPUT ;
    USE SIGNAL ;
    PORT
      LAYER M4 ;
        RECT  0 4.32 0.084 4.344 ;
    END
  END rx_payload[7]
  PIN rx_payload[80]
    DIRECTION INPUT ;
    USE SIGNAL ;
    PORT
      LAYER M4 ;
        RECT  0 11.424 0.084 11.448 ;
    END
  END rx_payload[80]
  PIN rx_payload[81]
    DIRECTION INPUT ;
    USE SIGNAL ;
    PORT
      LAYER M4 ;
        RECT  0 11.52 0.084 11.544 ;
    END
  END rx_payload[81]
  PIN rx_payload[82]
    DIRECTION INPUT ;
    USE SIGNAL ;
    PORT
      LAYER M4 ;
        RECT  0 11.616 0.084 11.64 ;
    END
  END rx_payload[82]
  PIN rx_payload[83]
    DIRECTION INPUT ;
    USE SIGNAL ;
    PORT
      LAYER M4 ;
        RECT  0 11.712 0.084 11.736 ;
    END
  END rx_payload[83]
  PIN rx_payload[84]
    DIRECTION INPUT ;
    USE SIGNAL ;
    PORT
      LAYER M4 ;
        RECT  0 11.808 0.084 11.832 ;
    END
  END rx_payload[84]
  PIN rx_payload[85]
    DIRECTION INPUT ;
    USE SIGNAL ;
    PORT
      LAYER M4 ;
        RECT  0 11.904 0.084 11.928 ;
    END
  END rx_payload[85]
  PIN rx_payload[86]
    DIRECTION INPUT ;
    USE SIGNAL ;
    PORT
      LAYER M4 ;
        RECT  0 12 0.084 12.024 ;
    END
  END rx_payload[86]
  PIN rx_payload[87]
    DIRECTION INPUT ;
    USE SIGNAL ;
    PORT
      LAYER M4 ;
        RECT  0 12.096 0.084 12.12 ;
    END
  END rx_payload[87]
  PIN rx_payload[88]
    DIRECTION INPUT ;
    USE SIGNAL ;
    PORT
      LAYER M4 ;
        RECT  0 12.192 0.084 12.216 ;
    END
  END rx_payload[88]
  PIN rx_payload[89]
    DIRECTION INPUT ;
    USE SIGNAL ;
    PORT
      LAYER M4 ;
        RECT  0 12.288 0.084 12.312 ;
    END
  END rx_payload[89]
  PIN rx_payload[8]
    DIRECTION INPUT ;
    USE SIGNAL ;
    PORT
      LAYER M4 ;
        RECT  0 4.416 0.084 4.44 ;
    END
  END rx_payload[8]
  PIN rx_payload[90]
    DIRECTION INPUT ;
    USE SIGNAL ;
    PORT
      LAYER M4 ;
        RECT  0 12.384 0.084 12.408 ;
    END
  END rx_payload[90]
  PIN rx_payload[91]
    DIRECTION INPUT ;
    USE SIGNAL ;
    PORT
      LAYER M4 ;
        RECT  0 12.528 0.084 12.552 ;
    END
  END rx_payload[91]
  PIN rx_payload[92]
    DIRECTION INPUT ;
    USE SIGNAL ;
    PORT
      LAYER M4 ;
        RECT  0 12.624 0.084 12.648 ;
    END
  END rx_payload[92]
  PIN rx_payload[93]
    DIRECTION INPUT ;
    USE SIGNAL ;
    PORT
      LAYER M4 ;
        RECT  0 12.72 0.084 12.744 ;
    END
  END rx_payload[93]
  PIN rx_payload[94]
    DIRECTION INPUT ;
    USE SIGNAL ;
    PORT
      LAYER M4 ;
        RECT  0 12.816 0.084 12.84 ;
    END
  END rx_payload[94]
  PIN rx_payload[95]
    DIRECTION INPUT ;
    USE SIGNAL ;
    PORT
      LAYER M4 ;
        RECT  0 12.912 0.084 12.936 ;
    END
  END rx_payload[95]
  PIN rx_payload[96]
    DIRECTION INPUT ;
    USE SIGNAL ;
    PORT
      LAYER M4 ;
        RECT  0 13.008 0.084 13.032 ;
    END
  END rx_payload[96]
  PIN rx_payload[97]
    DIRECTION INPUT ;
    USE SIGNAL ;
    PORT
      LAYER M4 ;
        RECT  0 13.104 0.084 13.128 ;
    END
  END rx_payload[97]
  PIN rx_payload[98]
    DIRECTION INPUT ;
    USE SIGNAL ;
    PORT
      LAYER M4 ;
        RECT  0 13.2 0.084 13.224 ;
    END
  END rx_payload[98]
  PIN rx_payload[99]
    DIRECTION INPUT ;
    USE SIGNAL ;
    PORT
      LAYER M4 ;
        RECT  0 13.296 0.084 13.32 ;
    END
  END rx_payload[99]
  PIN rx_payload[9]
    DIRECTION INPUT ;
    USE SIGNAL ;
    PORT
      LAYER M4 ;
        RECT  0 4.512 0.084 4.536 ;
    END
  END rx_payload[9]
  PIN VDD
    DIRECTION INOUT ;
    USE POWER ;
    PORT
      LAYER M5 ;
        RECT  40.392 2.151 40.512 95.049 ;
        RECT  34.992 2.151 35.112 95.049 ;
        RECT  29.592 2.151 29.712 95.049 ;
        RECT  24.192 2.151 24.312 95.049 ;
        RECT  18.792 2.151 18.912 95.049 ;
        RECT  13.392 2.151 13.512 95.049 ;
        RECT  7.992 2.151 8.112 95.049 ;
        RECT  2.592 2.151 2.712 95.049 ;
    END
  END VDD
  PIN VSS
    DIRECTION INOUT ;
    USE GROUND ;
    PORT
      LAYER M5 ;
        RECT  40.2 2.137 40.32 95.063 ;
        RECT  34.8 2.137 34.92 95.063 ;
        RECT  29.4 2.137 29.52 95.063 ;
        RECT  24 2.137 24.12 95.063 ;
        RECT  18.6 2.137 18.72 95.063 ;
        RECT  13.2 2.137 13.32 95.063 ;
        RECT  7.8 2.137 7.92 95.063 ;
        RECT  2.4 2.137 2.52 95.063 ;
    END
  END VSS
  OBS
    LAYER RVTN ;
     RECT  2.16 2.16 41.04 2.295 ;
     RECT  2.16 2.565 41.04 2.835 ;
     RECT  2.16 3.105 41.04 3.375 ;
     RECT  2.16 3.645 41.04 3.915 ;
     RECT  2.16 4.185 41.04 4.455 ;
     RECT  2.16 4.725 41.04 4.995 ;
     RECT  2.16 5.265 41.04 5.535 ;
     RECT  2.16 5.805 41.04 6.075 ;
     RECT  2.16 6.345 41.04 6.615 ;
     RECT  2.16 6.885 41.04 7.155 ;
     RECT  2.16 7.425 41.04 7.695 ;
     RECT  2.16 7.965 41.04 8.235 ;
     RECT  2.16 8.505 41.04 8.775 ;
     RECT  2.16 9.045 41.04 9.315 ;
     RECT  2.16 9.585 41.04 9.855 ;
     RECT  2.16 10.125 41.04 10.395 ;
     RECT  2.16 10.665 41.04 10.935 ;
     RECT  2.16 11.205 41.04 11.475 ;
     RECT  2.16 11.745 41.04 12.015 ;
     RECT  2.16 12.285 41.04 12.555 ;
     RECT  2.16 12.825 41.04 13.095 ;
     RECT  2.16 13.365 41.04 13.635 ;
     RECT  2.16 13.905 41.04 14.175 ;
     RECT  2.16 14.445 41.04 14.715 ;
     RECT  2.16 14.985 41.04 15.255 ;
     RECT  2.16 15.525 41.04 15.795 ;
     RECT  2.16 16.065 41.04 16.335 ;
     RECT  2.16 16.605 41.04 16.875 ;
     RECT  2.16 17.145 41.04 17.415 ;
     RECT  2.16 17.685 41.04 17.955 ;
     RECT  2.16 18.225 41.04 18.495 ;
     RECT  2.16 18.765 41.04 19.035 ;
     RECT  2.16 19.305 41.04 19.575 ;
     RECT  2.16 19.845 41.04 20.115 ;
     RECT  2.16 20.385 41.04 20.655 ;
     RECT  2.16 20.925 41.04 21.195 ;
     RECT  2.16 21.465 41.04 21.735 ;
     RECT  2.16 22.005 41.04 22.275 ;
     RECT  2.16 22.545 41.04 22.815 ;
     RECT  2.16 23.085 41.04 23.355 ;
     RECT  2.16 23.625 41.04 23.895 ;
     RECT  2.16 24.165 41.04 24.435 ;
     RECT  2.16 24.705 41.04 24.975 ;
     RECT  2.16 25.245 41.04 25.515 ;
     RECT  2.16 25.785 41.04 26.055 ;
     RECT  2.16 26.325 41.04 26.595 ;
     RECT  2.16 26.865 41.04 27.135 ;
     RECT  2.16 27.405 41.04 27.675 ;
     RECT  2.16 27.945 41.04 28.215 ;
     RECT  2.16 28.485 41.04 28.755 ;
     RECT  2.16 29.025 41.04 29.295 ;
     RECT  2.16 29.565 41.04 29.835 ;
     RECT  2.16 30.105 41.04 30.375 ;
     RECT  2.16 30.645 41.04 30.915 ;
     RECT  2.16 31.185 41.04 31.455 ;
     RECT  2.16 31.725 41.04 31.995 ;
     RECT  2.16 32.265 41.04 32.535 ;
     RECT  2.16 32.805 41.04 33.075 ;
     RECT  2.16 33.345 41.04 33.615 ;
     RECT  2.16 33.885 41.04 34.155 ;
     RECT  2.16 34.425 41.04 34.695 ;
     RECT  2.16 34.965 41.04 35.235 ;
     RECT  2.16 35.505 41.04 35.775 ;
     RECT  2.16 36.045 41.04 36.315 ;
     RECT  2.16 36.585 41.04 36.855 ;
     RECT  2.16 37.125 41.04 37.395 ;
     RECT  2.16 37.665 41.04 37.935 ;
     RECT  2.16 38.205 41.04 38.475 ;
     RECT  2.16 38.745 41.04 39.015 ;
     RECT  2.16 39.285 41.04 39.555 ;
     RECT  2.16 39.825 41.04 40.095 ;
     RECT  2.16 40.365 41.04 40.635 ;
     RECT  2.16 40.905 41.04 41.175 ;
     RECT  2.16 41.445 41.04 41.715 ;
     RECT  2.16 41.985 41.04 42.255 ;
     RECT  2.16 42.525 41.04 42.795 ;
     RECT  2.16 43.065 41.04 43.335 ;
     RECT  2.16 43.605 41.04 43.875 ;
     RECT  2.16 44.145 41.04 44.415 ;
     RECT  2.16 44.685 41.04 44.955 ;
     RECT  2.16 45.225 41.04 45.495 ;
     RECT  2.16 45.765 41.04 46.035 ;
     RECT  2.16 46.305 41.04 46.575 ;
     RECT  2.16 46.845 41.04 47.115 ;
     RECT  2.16 47.385 41.04 47.655 ;
     RECT  2.16 47.925 41.04 48.195 ;
     RECT  2.16 48.465 41.04 48.735 ;
     RECT  2.16 49.005 41.04 49.275 ;
     RECT  2.16 49.545 41.04 49.815 ;
     RECT  2.16 50.085 41.04 50.355 ;
     RECT  2.16 50.625 41.04 50.895 ;
     RECT  2.16 51.165 41.04 51.435 ;
     RECT  2.16 51.705 41.04 51.975 ;
     RECT  2.16 52.245 41.04 52.515 ;
     RECT  2.16 52.785 41.04 53.055 ;
     RECT  2.16 53.325 41.04 53.595 ;
     RECT  2.16 53.865 41.04 54.135 ;
     RECT  2.16 54.405 41.04 54.675 ;
     RECT  2.16 54.945 41.04 55.215 ;
     RECT  2.16 55.485 41.04 55.755 ;
     RECT  2.16 56.025 41.04 56.295 ;
     RECT  2.16 56.565 41.04 56.835 ;
     RECT  2.16 57.105 41.04 57.375 ;
     RECT  2.16 57.645 41.04 57.915 ;
     RECT  2.16 58.185 41.04 58.455 ;
     RECT  2.16 58.725 41.04 58.995 ;
     RECT  2.16 59.265 41.04 59.535 ;
     RECT  2.16 59.805 41.04 60.075 ;
     RECT  2.16 60.345 41.04 60.615 ;
     RECT  2.16 60.885 41.04 61.155 ;
     RECT  2.16 61.425 41.04 61.695 ;
     RECT  2.16 61.965 41.04 62.235 ;
     RECT  2.16 62.505 41.04 62.775 ;
     RECT  2.16 63.045 41.04 63.315 ;
     RECT  2.16 63.585 41.04 63.855 ;
     RECT  2.16 64.125 41.04 64.395 ;
     RECT  2.16 64.665 41.04 64.935 ;
     RECT  2.16 65.205 41.04 65.475 ;
     RECT  2.16 65.745 41.04 66.015 ;
     RECT  2.16 66.285 41.04 66.555 ;
     RECT  2.16 66.825 41.04 67.095 ;
     RECT  2.16 67.365 41.04 67.635 ;
     RECT  2.16 67.905 41.04 68.175 ;
     RECT  2.16 68.445 41.04 68.715 ;
     RECT  2.16 68.985 41.04 69.255 ;
     RECT  2.16 69.525 41.04 69.795 ;
     RECT  2.16 70.065 41.04 70.335 ;
     RECT  2.16 70.605 41.04 70.875 ;
     RECT  2.16 71.145 41.04 71.415 ;
     RECT  2.16 71.685 41.04 71.955 ;
     RECT  2.16 72.225 41.04 72.495 ;
     RECT  2.16 72.765 41.04 73.035 ;
     RECT  2.16 73.305 41.04 73.575 ;
     RECT  2.16 73.845 41.04 74.115 ;
     RECT  2.16 74.385 41.04 74.655 ;
     RECT  2.16 74.925 41.04 75.195 ;
     RECT  2.16 75.465 41.04 75.735 ;
     RECT  2.16 76.005 41.04 76.275 ;
     RECT  2.16 76.545 41.04 76.815 ;
     RECT  2.16 77.085 41.04 77.355 ;
     RECT  2.16 77.625 41.04 77.895 ;
     RECT  2.16 78.165 41.04 78.435 ;
     RECT  2.16 78.705 41.04 78.975 ;
     RECT  2.16 79.245 41.04 79.515 ;
     RECT  2.16 79.785 41.04 80.055 ;
     RECT  2.16 80.325 41.04 80.595 ;
     RECT  2.16 80.865 41.04 81.135 ;
     RECT  2.16 81.405 41.04 81.675 ;
     RECT  2.16 81.945 41.04 82.215 ;
     RECT  2.16 82.485 41.04 82.755 ;
     RECT  2.16 83.025 41.04 83.295 ;
     RECT  2.16 83.565 41.04 83.835 ;
     RECT  2.16 84.105 41.04 84.375 ;
     RECT  2.16 84.645 41.04 84.915 ;
     RECT  2.16 85.185 41.04 85.455 ;
     RECT  2.16 85.725 41.04 85.995 ;
     RECT  2.16 86.265 41.04 86.535 ;
     RECT  2.16 86.805 41.04 87.075 ;
     RECT  2.16 87.345 41.04 87.615 ;
     RECT  2.16 87.885 41.04 88.155 ;
     RECT  2.16 88.425 41.04 88.695 ;
     RECT  2.16 88.965 41.04 89.235 ;
     RECT  2.16 89.505 41.04 89.775 ;
     RECT  2.16 90.045 41.04 90.315 ;
     RECT  2.16 90.585 41.04 90.855 ;
     RECT  2.16 91.125 41.04 91.395 ;
     RECT  2.16 91.665 41.04 91.935 ;
     RECT  2.16 92.205 41.04 92.475 ;
     RECT  2.16 92.745 41.04 93.015 ;
     RECT  2.16 93.285 41.04 93.555 ;
     RECT  2.16 93.825 41.04 94.095 ;
     RECT  2.16 94.365 41.04 94.635 ;
     RECT  2.16 94.905 41.04 95.04 ;
    LAYER RVTP ;
     RECT  2.16 2.295 41.04 2.565 ;
     RECT  2.16 2.835 41.04 3.105 ;
     RECT  2.16 3.375 41.04 3.645 ;
     RECT  2.16 3.915 41.04 4.185 ;
     RECT  2.16 4.455 41.04 4.725 ;
     RECT  2.16 4.995 41.04 5.265 ;
     RECT  2.16 5.535 41.04 5.805 ;
     RECT  2.16 6.075 41.04 6.345 ;
     RECT  2.16 6.615 41.04 6.885 ;
     RECT  2.16 7.155 41.04 7.425 ;
     RECT  2.16 7.695 41.04 7.965 ;
     RECT  2.16 8.235 41.04 8.505 ;
     RECT  2.16 8.775 41.04 9.045 ;
     RECT  2.16 9.315 41.04 9.585 ;
     RECT  2.16 9.855 41.04 10.125 ;
     RECT  2.16 10.395 41.04 10.665 ;
     RECT  2.16 10.935 41.04 11.205 ;
     RECT  2.16 11.475 41.04 11.745 ;
     RECT  2.16 12.015 41.04 12.285 ;
     RECT  2.16 12.555 41.04 12.825 ;
     RECT  2.16 13.095 41.04 13.365 ;
     RECT  2.16 13.635 41.04 13.905 ;
     RECT  2.16 14.175 41.04 14.445 ;
     RECT  2.16 14.715 41.04 14.985 ;
     RECT  2.16 15.255 41.04 15.525 ;
     RECT  2.16 15.795 41.04 16.065 ;
     RECT  2.16 16.335 41.04 16.605 ;
     RECT  2.16 16.875 41.04 17.145 ;
     RECT  2.16 17.415 41.04 17.685 ;
     RECT  2.16 17.955 41.04 18.225 ;
     RECT  2.16 18.495 41.04 18.765 ;
     RECT  2.16 19.035 41.04 19.305 ;
     RECT  2.16 19.575 41.04 19.845 ;
     RECT  2.16 20.115 41.04 20.385 ;
     RECT  2.16 20.655 41.04 20.925 ;
     RECT  2.16 21.195 41.04 21.465 ;
     RECT  2.16 21.735 41.04 22.005 ;
     RECT  2.16 22.275 41.04 22.545 ;
     RECT  2.16 22.815 41.04 23.085 ;
     RECT  2.16 23.355 41.04 23.625 ;
     RECT  2.16 23.895 41.04 24.165 ;
     RECT  2.16 24.435 41.04 24.705 ;
     RECT  2.16 24.975 41.04 25.245 ;
     RECT  2.16 25.515 41.04 25.785 ;
     RECT  2.16 26.055 41.04 26.325 ;
     RECT  2.16 26.595 41.04 26.865 ;
     RECT  2.16 27.135 41.04 27.405 ;
     RECT  2.16 27.675 41.04 27.945 ;
     RECT  2.16 28.215 41.04 28.485 ;
     RECT  2.16 28.755 41.04 29.025 ;
     RECT  2.16 29.295 41.04 29.565 ;
     RECT  2.16 29.835 41.04 30.105 ;
     RECT  2.16 30.375 41.04 30.645 ;
     RECT  2.16 30.915 41.04 31.185 ;
     RECT  2.16 31.455 41.04 31.725 ;
     RECT  2.16 31.995 41.04 32.265 ;
     RECT  2.16 32.535 41.04 32.805 ;
     RECT  2.16 33.075 41.04 33.345 ;
     RECT  2.16 33.615 41.04 33.885 ;
     RECT  2.16 34.155 41.04 34.425 ;
     RECT  2.16 34.695 41.04 34.965 ;
     RECT  2.16 35.235 41.04 35.505 ;
     RECT  2.16 35.775 41.04 36.045 ;
     RECT  2.16 36.315 41.04 36.585 ;
     RECT  2.16 36.855 41.04 37.125 ;
     RECT  2.16 37.395 41.04 37.665 ;
     RECT  2.16 37.935 41.04 38.205 ;
     RECT  2.16 38.475 41.04 38.745 ;
     RECT  2.16 39.015 41.04 39.285 ;
     RECT  2.16 39.555 41.04 39.825 ;
     RECT  2.16 40.095 41.04 40.365 ;
     RECT  2.16 40.635 41.04 40.905 ;
     RECT  2.16 41.175 41.04 41.445 ;
     RECT  2.16 41.715 41.04 41.985 ;
     RECT  2.16 42.255 41.04 42.525 ;
     RECT  2.16 42.795 41.04 43.065 ;
     RECT  2.16 43.335 41.04 43.605 ;
     RECT  2.16 43.875 41.04 44.145 ;
     RECT  2.16 44.415 41.04 44.685 ;
     RECT  2.16 44.955 41.04 45.225 ;
     RECT  2.16 45.495 41.04 45.765 ;
     RECT  2.16 46.035 41.04 46.305 ;
     RECT  2.16 46.575 41.04 46.845 ;
     RECT  2.16 47.115 41.04 47.385 ;
     RECT  2.16 47.655 41.04 47.925 ;
     RECT  2.16 48.195 41.04 48.465 ;
     RECT  2.16 48.735 41.04 49.005 ;
     RECT  2.16 49.275 41.04 49.545 ;
     RECT  2.16 49.815 41.04 50.085 ;
     RECT  2.16 50.355 41.04 50.625 ;
     RECT  2.16 50.895 41.04 51.165 ;
     RECT  2.16 51.435 41.04 51.705 ;
     RECT  2.16 51.975 41.04 52.245 ;
     RECT  2.16 52.515 41.04 52.785 ;
     RECT  2.16 53.055 41.04 53.325 ;
     RECT  2.16 53.595 41.04 53.865 ;
     RECT  2.16 54.135 41.04 54.405 ;
     RECT  2.16 54.675 41.04 54.945 ;
     RECT  2.16 55.215 41.04 55.485 ;
     RECT  2.16 55.755 41.04 56.025 ;
     RECT  2.16 56.295 41.04 56.565 ;
     RECT  2.16 56.835 41.04 57.105 ;
     RECT  2.16 57.375 41.04 57.645 ;
     RECT  2.16 57.915 41.04 58.185 ;
     RECT  2.16 58.455 41.04 58.725 ;
     RECT  2.16 58.995 41.04 59.265 ;
     RECT  2.16 59.535 41.04 59.805 ;
     RECT  2.16 60.075 41.04 60.345 ;
     RECT  2.16 60.615 41.04 60.885 ;
     RECT  2.16 61.155 41.04 61.425 ;
     RECT  2.16 61.695 41.04 61.965 ;
     RECT  2.16 62.235 41.04 62.505 ;
     RECT  2.16 62.775 41.04 63.045 ;
     RECT  2.16 63.315 41.04 63.585 ;
     RECT  2.16 63.855 41.04 64.125 ;
     RECT  2.16 64.395 41.04 64.665 ;
     RECT  2.16 64.935 41.04 65.205 ;
     RECT  2.16 65.475 41.04 65.745 ;
     RECT  2.16 66.015 41.04 66.285 ;
     RECT  2.16 66.555 41.04 66.825 ;
     RECT  2.16 67.095 41.04 67.365 ;
     RECT  2.16 67.635 41.04 67.905 ;
     RECT  2.16 68.175 41.04 68.445 ;
     RECT  2.16 68.715 41.04 68.985 ;
     RECT  2.16 69.255 41.04 69.525 ;
     RECT  2.16 69.795 41.04 70.065 ;
     RECT  2.16 70.335 41.04 70.605 ;
     RECT  2.16 70.875 41.04 71.145 ;
     RECT  2.16 71.415 41.04 71.685 ;
     RECT  2.16 71.955 41.04 72.225 ;
     RECT  2.16 72.495 41.04 72.765 ;
     RECT  2.16 73.035 41.04 73.305 ;
     RECT  2.16 73.575 41.04 73.845 ;
     RECT  2.16 74.115 41.04 74.385 ;
     RECT  2.16 74.655 41.04 74.925 ;
     RECT  2.16 75.195 41.04 75.465 ;
     RECT  2.16 75.735 41.04 76.005 ;
     RECT  2.16 76.275 41.04 76.545 ;
     RECT  2.16 76.815 41.04 77.085 ;
     RECT  2.16 77.355 41.04 77.625 ;
     RECT  2.16 77.895 41.04 78.165 ;
     RECT  2.16 78.435 41.04 78.705 ;
     RECT  2.16 78.975 41.04 79.245 ;
     RECT  2.16 79.515 41.04 79.785 ;
     RECT  2.16 80.055 41.04 80.325 ;
     RECT  2.16 80.595 41.04 80.865 ;
     RECT  2.16 81.135 41.04 81.405 ;
     RECT  2.16 81.675 41.04 81.945 ;
     RECT  2.16 82.215 41.04 82.485 ;
     RECT  2.16 82.755 41.04 83.025 ;
     RECT  2.16 83.295 41.04 83.565 ;
     RECT  2.16 83.835 41.04 84.105 ;
     RECT  2.16 84.375 41.04 84.645 ;
     RECT  2.16 84.915 41.04 85.185 ;
     RECT  2.16 85.455 41.04 85.725 ;
     RECT  2.16 85.995 41.04 86.265 ;
     RECT  2.16 86.535 41.04 86.805 ;
     RECT  2.16 87.075 41.04 87.345 ;
     RECT  2.16 87.615 41.04 87.885 ;
     RECT  2.16 88.155 41.04 88.425 ;
     RECT  2.16 88.695 41.04 88.965 ;
     RECT  2.16 89.235 41.04 89.505 ;
     RECT  2.16 89.775 41.04 90.045 ;
     RECT  2.16 90.315 41.04 90.585 ;
     RECT  2.16 90.855 41.04 91.125 ;
     RECT  2.16 91.395 41.04 91.665 ;
     RECT  2.16 91.935 41.04 92.205 ;
     RECT  2.16 92.475 41.04 92.745 ;
     RECT  2.16 93.015 41.04 93.285 ;
     RECT  2.16 93.555 41.04 93.825 ;
     RECT  2.16 94.095 41.04 94.365 ;
     RECT  2.16 94.635 41.04 94.905 ;
    LAYER M1 ;
     RECT  2.16 2.151 41.04 95.049 ;
    LAYER M2 ;
     RECT  0.031 9.171 0.067 9.189 ;
     RECT  0.031 6.822 0.103 6.84 ;
     RECT  0.031 7.902 0.103 7.92 ;
     RECT  0.067 8.82 0.131 9.189 ;
     RECT  0.067 54.45 0.139 54.468 ;
     RECT  0.103 55.26 0.139 55.818 ;
     RECT  0.139 54.45 0.167 55.818 ;
     RECT  0.103 50.832 0.175 50.85 ;
     RECT  0.131 8.82 0.203 8.838 ;
     RECT  0.175 50.751 0.203 50.85 ;
     RECT  0.103 56.844 0.203 56.862 ;
     RECT  0.139 3.384 0.211 3.402 ;
     RECT  0.203 50.751 0.275 50.769 ;
     RECT  0.211 3.384 0.427 3.978 ;
     RECT  0.211 4.932 0.427 4.95 ;
     RECT  0.427 3.384 0.535 4.95 ;
     RECT  0.103 6.822 0.535 7.92 ;
     RECT  0.103 53.37 0.535 53.388 ;
     RECT  0.535 6.696 0.823 7.92 ;
     RECT  0.103 31.932 0.895 31.95 ;
     RECT  0.139 37.872 0.931 37.89 ;
     RECT  0.103 39.06 0.931 39.078 ;
     RECT  0.067 44.424 0.967 44.442 ;
     RECT  0.031 48.942 1.039 48.96 ;
     RECT  1.147 51.21 1.183 51.228 ;
     RECT  0.859 47.592 1.399 47.61 ;
     RECT  1.399 47.052 1.435 47.61 ;
     RECT  0.535 53.298 1.435 53.388 ;
     RECT  0.859 45.432 1.471 45.45 ;
     RECT  1.435 47.052 1.471 47.88 ;
     RECT  0.931 28.422 1.507 28.44 ;
     RECT  0.931 37.872 1.507 39.078 ;
     RECT  1.435 52.992 1.543 53.388 ;
     RECT  0.175 41.76 1.579 41.778 ;
     RECT  1.579 41.76 1.651 42.21 ;
     RECT  0.067 43.002 1.651 43.02 ;
     RECT  1.507 37.44 2.011 39.078 ;
     RECT  1.471 45.432 2.011 45.72 ;
     RECT  0.823 6.696 2.083 8.496 ;
     RECT  0.895 35.046 2.119 35.064 ;
     RECT  2.047 35.982 2.119 36 ;
     RECT  2.083 6.696 2.155 9.234 ;
     RECT  0.535 3.384 2.16 5.49 ;
     RECT  2.155 6.696 2.16 9.504 ;
     RECT  1.543 27.342 2.16 27.36 ;
     RECT  1.507 28.422 2.16 28.98 ;
     RECT  0.895 31.932 2.16 32.454 ;
     RECT  0.211 33.516 2.16 33.534 ;
     RECT  2.119 35.046 2.16 36 ;
     RECT  2.011 37.332 2.16 39.078 ;
     RECT  1.651 41.76 2.16 43.02 ;
     RECT  0.967 44.19 2.16 44.442 ;
     RECT  2.011 45.27 2.16 45.72 ;
     RECT  1.471 46.89 2.16 47.88 ;
     RECT  1.039 48.78 2.16 48.96 ;
     RECT  1.399 50.13 2.16 50.148 ;
     RECT  1.183 51.21 2.16 51.498 ;
     RECT  1.543 52.83 2.16 53.388 ;
     RECT  0.167 54.99 2.16 55.818 ;
     RECT  2.16 2.151 4.135 95.049 ;
     RECT  4.135 2.034 5.423 95.049 ;
     RECT  5.423 2.106 5.999 95.049 ;
     RECT  5.999 2.151 6.835 95.049 ;
     RECT  6.835 2.034 7.519 95.049 ;
     RECT  7.519 1.962 9.815 95.049 ;
     RECT  9.815 2.034 12.803 95.049 ;
     RECT  12.803 2.106 13.055 95.049 ;
     RECT  13.055 2.151 41.04 95.049 ;
    LAYER M3 ;
     RECT  4.284 0.091 4.302 0.523 ;
     RECT  5.04 0.091 5.202 0.523 ;
     RECT  9.396 0.091 9.414 0.523 ;
     RECT  10.188 0.091 10.206 0.523 ;
     RECT  11.34 0.091 12.618 0.523 ;
     RECT  11.34 0.523 12.762 0.571 ;
     RECT  15.084 0.091 17.046 0.571 ;
     RECT  7.02 0.571 8.19 1.051 ;
     RECT  9.144 0.523 9.414 1.099 ;
     RECT  10.152 0.523 10.566 1.099 ;
     RECT  11.34 0.571 13.05 1.099 ;
     RECT  13.896 0.475 13.914 1.099 ;
     RECT  14.904 0.571 17.046 1.099 ;
     RECT  7.02 1.051 8.226 1.147 ;
     RECT  9.144 1.099 10.566 1.147 ;
     RECT  11.34 1.099 17.046 1.147 ;
     RECT  4.284 0.523 5.202 1.723 ;
     RECT  6.084 0.571 6.102 1.723 ;
     RECT  7.02 1.147 17.046 1.723 ;
     RECT  30.168 1.675 30.186 1.723 ;
     RECT  30.168 1.723 30.726 2.143 ;
     RECT  3.744 1.723 17.046 2.219 ;
     RECT  2.415 2.143 2.505 2.413 ;
     RECT  18.615 2.143 18.705 2.413 ;
     RECT  24.015 2.143 24.105 2.413 ;
     RECT  34.815 2.143 34.905 2.413 ;
     RECT  40.215 2.143 40.305 2.413 ;
     RECT  3.96 2.219 17.046 2.525 ;
     RECT  2.415 2.413 2.697 2.605 ;
     RECT  17.028 2.525 17.046 2.759 ;
     RECT  29.415 2.143 30.726 2.759 ;
     RECT  2.415 2.605 3.222 3.145 ;
     RECT  2.34 3.145 3.222 3.181 ;
     RECT  3.96 2.525 15.966 3.181 ;
     RECT  33.3 1.099 33.318 3.181 ;
     RECT  2.34 3.181 15.966 3.307 ;
     RECT  17.1 2.803 17.118 3.379 ;
     RECT  31.608 3.307 31.626 3.451 ;
     RECT  2.304 3.307 15.966 3.569 ;
     RECT  29.415 2.759 30.69 3.577 ;
     RECT  31.608 3.451 32.094 3.577 ;
     RECT  32.904 3.181 33.318 3.577 ;
     RECT  31.608 3.577 33.318 3.605 ;
     RECT  0.144 3.379 0.162 3.643 ;
     RECT  0.108 3.643 0.162 3.685 ;
     RECT  26.784 3.613 26.802 3.749 ;
     RECT  2.304 3.569 13.806 3.835 ;
     RECT  31.608 3.605 32.922 3.839 ;
     RECT  33.66 3.721 33.678 3.839 ;
     RECT  17.1 3.379 17.586 3.847 ;
     RECT  32.76 3.839 32.922 3.911 ;
     RECT  2.088 3.835 13.806 4.027 ;
     RECT  1.728 4.027 13.806 4.109 ;
     RECT  17.064 3.847 17.586 4.109 ;
     RECT  14.544 3.569 15.966 4.117 ;
     RECT  17.064 4.109 17.082 4.117 ;
     RECT  1.728 4.109 13.497 4.123 ;
     RECT  14.544 4.117 17.082 4.145 ;
     RECT  14.544 4.145 16.362 4.157 ;
     RECT  29.415 3.577 30.834 4.261 ;
     RECT  31.608 3.839 31.77 4.261 ;
     RECT  29.415 4.261 31.77 4.379 ;
     RECT  30.672 4.379 31.122 4.451 ;
     RECT  1.512 4.123 13.497 4.919 ;
     RECT  14.544 4.157 15.966 5.071 ;
     RECT  3.672 4.919 13.497 5.261 ;
     RECT  32.904 3.911 32.922 5.261 ;
     RECT  14.4 5.071 15.966 5.305 ;
     RECT  3.672 5.261 9.882 5.459 ;
     RECT  3.672 5.459 9.738 5.603 ;
     RECT  0.108 3.685 0.558 5.789 ;
     RECT  3.672 5.603 9.702 5.809 ;
     RECT  0.108 5.789 0.234 5.885 ;
     RECT  10.836 5.261 13.497 5.999 ;
     RECT  1.512 4.919 2.697 6.007 ;
     RECT  3.42 5.809 9.702 6.007 ;
     RECT  30.672 4.451 30.69 6.107 ;
     RECT  13.032 5.999 13.497 6.151 ;
     RECT  14.22 5.305 15.966 6.151 ;
     RECT  10.836 5.999 12.078 6.269 ;
     RECT  1.512 6.007 9.702 6.539 ;
     RECT  10.548 6.421 10.566 6.539 ;
     RECT  11.376 6.269 12.042 6.539 ;
     RECT  13.032 6.151 15.966 6.539 ;
     RECT  0.108 5.885 0.198 6.691 ;
     RECT  0.108 6.691 0.558 6.763 ;
     RECT  0.108 6.763 0.594 6.781 ;
     RECT  1.512 6.539 9.126 6.809 ;
     RECT  11.376 6.539 11.466 6.809 ;
     RECT  0.108 6.781 0.666 6.817 ;
     RECT  0.036 6.817 0.666 6.845 ;
     RECT  29.415 4.379 29.898 6.881 ;
     RECT  0.036 6.845 0.558 6.893 ;
     RECT  4.032 6.809 4.122 6.989 ;
     RECT  6.156 6.809 9.126 7.079 ;
     RECT  13.215 6.539 15.966 7.079 ;
     RECT  4.032 6.989 4.05 7.115 ;
     RECT  13.215 7.079 15.03 7.115 ;
     RECT  6.444 7.079 9.126 7.187 ;
     RECT  6.912 7.187 9.126 7.223 ;
     RECT  1.512 6.809 3.114 7.339 ;
     RECT  5.148 6.809 5.166 7.385 ;
     RECT  7.38 7.223 9.126 7.385 ;
     RECT  7.416 7.385 8.838 7.457 ;
     RECT  0.036 6.893 0.126 7.469 ;
     RECT  1.404 7.339 3.114 7.627 ;
     RECT  7.815 7.457 8.838 7.691 ;
     RECT  13.215 7.115 14.886 7.691 ;
     RECT  7.815 7.691 8.766 7.763 ;
     RECT  15.948 7.079 15.966 7.889 ;
     RECT  0.036 7.469 0.054 7.925 ;
     RECT  0.864 7.627 3.114 8.473 ;
     RECT  0.828 8.473 3.114 8.683 ;
     RECT  0.144 8.683 3.114 8.815 ;
     RECT  0.072 8.815 3.114 9.166 ;
     RECT  0.036 9.166 3.114 10.201 ;
     RECT  15.732 22.075 15.75 22.171 ;
     RECT  15.408 22.171 15.75 22.271 ;
     RECT  15.732 22.271 15.75 22.469 ;
     RECT  13.215 7.691 14.562 23.179 ;
     RECT  12.816 23.179 14.562 23.317 ;
     RECT  12.492 23.317 14.562 23.357 ;
     RECT  13.215 23.357 14.562 24.469 ;
     RECT  12.816 24.469 14.562 24.509 ;
     RECT  11.268 24.379 11.286 24.571 ;
     RECT  11.268 24.571 11.358 24.809 ;
     RECT  11.268 24.809 11.286 24.907 ;
     RECT  10.98 24.907 11.286 24.971 ;
     RECT  10.98 24.971 10.998 25.169 ;
     RECT  0.036 10.201 3.438 37.597 ;
     RECT  0.036 37.597 3.762 37.895 ;
     RECT  0.036 37.895 0.09 39.055 ;
     RECT  0.828 37.895 3.762 39.055 ;
     RECT  13.215 24.509 14.562 39.515 ;
     RECT  0.036 39.055 3.762 41.071 ;
     RECT  4.5 7.897 4.518 41.071 ;
     RECT  0.036 41.071 4.518 41.369 ;
     RECT  14.544 39.515 14.562 41.639 ;
     RECT  0.036 41.369 4.086 41.711 ;
     RECT  0.036 41.711 3.942 44.879 ;
     RECT  18.615 2.413 18.897 47.899 ;
     RECT  17.892 47.899 18.897 48.119 ;
     RECT  17.568 48.127 17.586 48.173 ;
     RECT  0.036 44.879 3.51 48.965 ;
     RECT  26.748 4.153 26.766 49.199 ;
     RECT  26.64 49.351 26.658 49.469 ;
     RECT  25.776 49.243 25.794 49.505 ;
     RECT  25.848 49.621 25.938 49.739 ;
     RECT  0.072 48.965 3.51 50.045 ;
     RECT  0.072 50.045 3.438 52.475 ;
     RECT  0.072 52.475 3.402 54.473 ;
     RECT  0.144 54.473 3.402 54.599 ;
     RECT  0.144 54.599 3.366 54.605 ;
     RECT  0.144 54.605 3.294 55.255 ;
     RECT  0.108 55.255 3.294 55.613 ;
     RECT  0.108 55.613 1.566 55.997 ;
     RECT  2.34 55.613 3.294 56.635 ;
     RECT  0.108 55.997 1.494 56.867 ;
     RECT  2.304 56.635 3.294 56.923 ;
     RECT  0.18 56.867 1.494 57.005 ;
     RECT  2.232 56.923 3.294 57.065 ;
     RECT  2.415 57.065 3.294 57.209 ;
     RECT  0.828 57.005 1.494 80.573 ;
     RECT  1.476 80.573 1.494 81.773 ;
     RECT  24.015 2.413 24.297 92.923 ;
     RECT  25.848 49.739 25.866 93.479 ;
     RECT  24.015 92.923 24.966 93.631 ;
     RECT  24.015 93.631 25.11 94.019 ;
     RECT  24.015 94.019 25.002 94.685 ;
     RECT  2.415 57.209 2.697 94.787 ;
     RECT  7.815 7.763 8.097 94.787 ;
     RECT  13.215 39.515 13.497 94.787 ;
     RECT  18.615 48.119 18.897 94.787 ;
     RECT  24.015 94.685 24.297 94.787 ;
     RECT  29.415 6.881 29.697 94.787 ;
     RECT  34.815 2.413 35.097 94.787 ;
     RECT  40.215 2.413 40.497 94.787 ;
     RECT  2.415 94.787 2.505 95.057 ;
     RECT  7.815 94.787 7.905 95.057 ;
     RECT  13.215 94.787 13.305 95.057 ;
     RECT  18.615 94.787 18.705 95.057 ;
     RECT  24.015 94.787 24.105 95.057 ;
     RECT  29.415 94.787 29.505 95.057 ;
     RECT  34.815 94.787 34.905 95.057 ;
     RECT  40.215 94.787 40.305 95.057 ;
    LAYER M4 ;
     RECT  0.06 53.52 0.136 56.952 ;
     RECT  0.06 3.648 0.137 9.336 ;
     RECT  0.137 3.744 0.209 9.096 ;
     RECT  0.06 80.544 0.857 80.568 ;
     RECT  0.136 53.52 1.181 57 ;
     RECT  1.181 53.712 1.217 57 ;
     RECT  0.209 3.84 2.408 9.096 ;
     RECT  2.293 40.032 2.408 40.056 ;
     RECT  2.293 44.448 2.408 44.472 ;
     RECT  1.217 53.808 2.408 57 ;
     RECT  0.06 81.744 2.408 81.768 ;
     RECT  2.408 2.148 2.512 95.052 ;
     RECT  2.512 2.418 2.704 94.782 ;
     RECT  2.704 54.48 2.801 55.8 ;
     RECT  2.704 45.696 2.819 45.816 ;
     RECT  2.704 52.32 2.819 53.352 ;
     RECT  2.704 2.736 2.837 7.176 ;
     RECT  2.704 41.376 2.837 41.4 ;
     RECT  2.819 52.32 2.845 53.016 ;
     RECT  2.704 8.544 2.867 9.144 ;
     RECT  2.819 45.792 2.867 45.816 ;
     RECT  2.867 9.072 2.909 9.096 ;
     RECT  2.704 50.688 2.981 50.712 ;
     RECT  2.845 52.896 3.053 53.016 ;
     RECT  2.801 54.48 3.125 54.888 ;
     RECT  2.837 4.848 3.299 5.544 ;
     RECT  3.125 54.48 3.305 54.6 ;
     RECT  3.305 54.576 3.377 54.6 ;
     RECT  3.733 1.728 3.816 1.752 ;
     RECT  2.837 2.736 3.816 3.72 ;
     RECT  3.299 5.088 4.453 5.544 ;
     RECT  2.837 6.576 4.453 7.176 ;
     RECT  4.117 0.096 4.489 0.12 ;
     RECT  3.816 1.728 4.499 3.72 ;
     RECT  4.499 1.728 4.565 1.848 ;
     RECT  4.489 0.096 4.645 0.552 ;
     RECT  4.453 5.088 4.844 7.176 ;
     RECT  4.844 4.896 5.177 7.176 ;
     RECT  4.645 0.096 5.267 0.6 ;
     RECT  5.177 4.896 5.321 6.744 ;
     RECT  4.565 1.728 5.677 1.8 ;
     RECT  4.499 2.88 5.677 3.72 ;
     RECT  5.321 4.896 5.677 5.16 ;
     RECT  5.677 1.728 5.825 5.16 ;
     RECT  5.321 6.192 6.833 6.744 ;
     RECT  6.833 6.624 6.865 6.744 ;
     RECT  5.825 1.728 6.937 3.48 ;
     RECT  6.937 1.728 6.997 3.912 ;
     RECT  5.825 4.896 6.997 5.16 ;
     RECT  6.865 6.624 7.369 6.84 ;
     RECT  6.997 1.728 7.441 5.16 ;
     RECT  5.267 0.576 7.573 0.6 ;
     RECT  7.441 1.68 7.573 5.16 ;
     RECT  7.573 0.576 7.808 5.16 ;
     RECT  7.369 6.624 7.808 7.368 ;
     RECT  7.045 23.088 7.808 23.112 ;
     RECT  7.141 24.912 7.808 24.936 ;
     RECT  7.808 0.576 7.912 95.052 ;
     RECT  7.912 0.576 8.104 94.782 ;
     RECT  8.104 3.888 8.201 5.064 ;
     RECT  8.104 0.576 9.116 2.808 ;
     RECT  8.201 3.888 9.169 3.912 ;
     RECT  8.201 5.04 9.169 5.064 ;
     RECT  9.116 0.528 9.341 2.808 ;
     RECT  8.104 24.912 9.349 24.936 ;
     RECT  9.169 3.888 9.395 5.064 ;
     RECT  9.395 3.888 9.731 3.96 ;
     RECT  9.341 0.096 9.929 2.808 ;
     RECT  9.929 0.096 10.217 2.28 ;
     RECT  10.217 0.528 10.643 2.28 ;
     RECT  9.349 24.576 11.009 24.936 ;
     RECT  10.643 1.104 11.027 2.28 ;
     RECT  11.027 1.68 11.077 2.28 ;
     RECT  11.077 1.68 11.219 2.904 ;
     RECT  11.009 24.576 11.228 24.792 ;
     RECT  8.104 23.184 11.269 23.208 ;
     RECT  11.228 24.384 11.315 24.792 ;
     RECT  11.315 24.576 11.369 24.792 ;
     RECT  11.219 1.728 11.473 2.904 ;
     RECT  9.731 3.888 11.473 3.912 ;
     RECT  11.473 1.728 12.131 3.912 ;
     RECT  11.329 0.096 12.509 0.12 ;
     RECT  12.509 0.096 12.673 0.6 ;
     RECT  11.369 24.768 12.757 24.792 ;
     RECT  12.131 2.784 13.021 3.912 ;
     RECT  12.131 1.728 13.093 1.752 ;
     RECT  13.021 2.784 13.093 4.152 ;
     RECT  13.093 1.728 13.208 4.152 ;
     RECT  11.269 23.184 13.208 23.352 ;
     RECT  12.757 24.48 13.208 24.792 ;
     RECT  12.757 49.248 13.208 49.272 ;
     RECT  13.208 1.728 13.312 95.052 ;
     RECT  13.312 1.728 13.504 94.782 ;
     RECT  12.673 0.24 13.667 0.6 ;
     RECT  13.504 1.728 13.667 4.152 ;
     RECT  13.667 0.48 13.676 0.6 ;
     RECT  13.667 1.728 13.676 3.912 ;
     RECT  13.676 0.48 13.955 3.912 ;
     RECT  13.955 0.576 14.147 3.912 ;
     RECT  14.147 2.832 14.243 3.912 ;
     RECT  14.147 0.576 14.339 1.8 ;
     RECT  14.243 3.312 14.435 3.912 ;
     RECT  14.339 1.68 14.579 1.8 ;
     RECT  14.435 3.888 14.712 3.912 ;
     RECT  14.712 3.888 14.861 4.152 ;
     RECT  14.339 0.576 14.977 0.6 ;
     RECT  15.397 22.176 15.637 22.2 ;
     RECT  15.637 22.08 15.683 22.2 ;
     RECT  13.504 23.328 15.683 23.352 ;
     RECT  15.683 22.08 15.761 22.104 ;
     RECT  15.073 0.096 15.805 0.168 ;
     RECT  14.579 1.728 16.301 1.8 ;
     RECT  16.301 1.728 16.661 1.752 ;
     RECT  15.805 0.096 17.057 0.12 ;
     RECT  15.637 47.904 17.557 47.928 ;
     RECT  14.861 4.128 18.608 4.152 ;
     RECT  17.557 47.904 18.608 48.168 ;
     RECT  13.504 49.248 18.608 49.272 ;
     RECT  18.608 2.148 18.712 95.052 ;
     RECT  18.712 2.418 18.904 94.782 ;
     RECT  18.904 48.144 21.539 48.168 ;
     RECT  18.904 4.128 24.008 4.152 ;
     RECT  18.904 49.248 24.008 49.272 ;
     RECT  24.008 2.148 24.112 95.052 ;
     RECT  24.112 2.418 24.304 94.782 ;
     RECT  24.304 92.928 25.021 92.952 ;
     RECT  24.304 94.656 25.043 94.68 ;
     RECT  24.304 49.248 25.805 49.272 ;
     RECT  24.304 4.128 29.408 4.152 ;
     RECT  29.408 2.148 29.512 95.052 ;
     RECT  29.512 2.148 29.704 94.782 ;
     RECT  29.704 3.6 30.227 4.152 ;
     RECT  30.157 1.68 30.275 1.704 ;
     RECT  30.668 1.728 30.755 1.752 ;
     RECT  30.227 3.6 32.249 3.624 ;
     RECT  33.26 1.104 33.347 1.128 ;
     RECT  34.808 2.148 34.912 95.052 ;
     RECT  34.912 2.418 35.104 94.782 ;
     RECT  40.208 2.148 40.312 95.052 ;
     RECT  40.312 2.418 40.504 94.782 ;
    LAYER M5 ;
     RECT  3.744 0.016 16.68 0.131 ;
     RECT  33.312 0.016 33.336 1.139 ;
     RECT  30.24 0.016 30.744 1.715 ;
     RECT  3.744 0.131 16.584 1.763 ;
     RECT  30.72 1.715 30.744 1.763 ;
     RECT  3.84 1.763 9.72 1.811 ;
     RECT  10.704 1.763 16.248 1.811 ;
     RECT  2.4 2.137 2.52 2.151 ;
     RECT  18.6 2.137 18.72 2.151 ;
     RECT  24 2.137 24.12 2.151 ;
     RECT  34.8 2.137 34.92 2.151 ;
     RECT  40.2 2.137 40.32 2.151 ;
     RECT  3.936 1.811 9.72 2.339 ;
     RECT  11.088 1.811 14.232 2.819 ;
     RECT  11.088 2.819 11.736 2.867 ;
     RECT  11.088 2.867 11.64 2.915 ;
     RECT  12.816 2.819 14.232 3.301 ;
     RECT  3.936 2.339 8.112 3.349 ;
     RECT  11.616 2.915 11.64 3.443 ;
     RECT  12.816 3.301 14.424 3.443 ;
     RECT  12.912 3.443 14.424 3.491 ;
     RECT  29.4 2.137 29.712 3.589 ;
     RECT  2.4 2.151 2.712 3.685 ;
     RECT  3.744 3.349 8.112 3.685 ;
     RECT  13.2 3.491 14.424 3.877 ;
     RECT  13.2 3.877 14.808 3.923 ;
     RECT  9.696 2.339 9.72 3.971 ;
     RECT  14.784 3.923 14.808 4.117 ;
     RECT  13.2 3.923 13.656 4.163 ;
     RECT  14.784 4.117 15.672 4.163 ;
     RECT  29.4 3.589 30.216 4.163 ;
     RECT  2.4 3.685 8.112 4.883 ;
     RECT  3.936 4.883 8.112 5.171 ;
     RECT  4.752 5.171 5.688 5.747 ;
     RECT  5.664 5.747 5.688 6.323 ;
     RECT  2.4 4.883 2.712 8.533 ;
     RECT  2.4 8.533 2.856 9.061 ;
     RECT  7.056 5.171 8.112 23.123 ;
     RECT  11.28 23.317 11.304 24.419 ;
     RECT  13.2 4.163 13.512 24.469 ;
     RECT  9.36 4.261 9.384 24.611 ;
     RECT  7.152 23.123 8.112 24.947 ;
     RECT  2.304 9.061 2.856 44.483 ;
     RECT  2.4 44.483 2.856 45.827 ;
     RECT  15.648 4.163 15.672 47.939 ;
     RECT  24 2.151 24.312 49.237 ;
     RECT  12.768 24.469 13.512 49.283 ;
     RECT  2.4 45.827 2.712 52.309 ;
     RECT  2.4 52.309 2.808 53.363 ;
     RECT  24 49.237 24.984 92.963 ;
     RECT  24 92.963 24.312 94.645 ;
     RECT  2.4 53.363 2.712 95.049 ;
     RECT  7.8 24.947 8.112 95.049 ;
     RECT  13.2 49.283 13.512 95.049 ;
     RECT  18.6 2.151 18.912 95.049 ;
     RECT  29.4 4.163 29.712 95.049 ;
     RECT  34.8 2.151 35.112 95.049 ;
     RECT  40.2 2.151 40.512 95.049 ;
     RECT  2.4 95.049 2.52 95.063 ;
     RECT  7.8 95.049 7.92 95.063 ;
     RECT  13.2 95.049 13.32 95.063 ;
     RECT  18.6 95.049 18.72 95.063 ;
     RECT  24 94.645 25.032 95.063 ;
     RECT  29.4 95.049 29.52 95.063 ;
     RECT  34.8 95.049 34.92 95.063 ;
     RECT  40.2 95.049 40.32 95.063 ;
     RECT  21.504 48.133 21.528 97.168 ;
     RECT  25.008 95.063 25.032 97.168 ;
  END
END qfd_mu_ctx_rx_die
END LIBRARY
